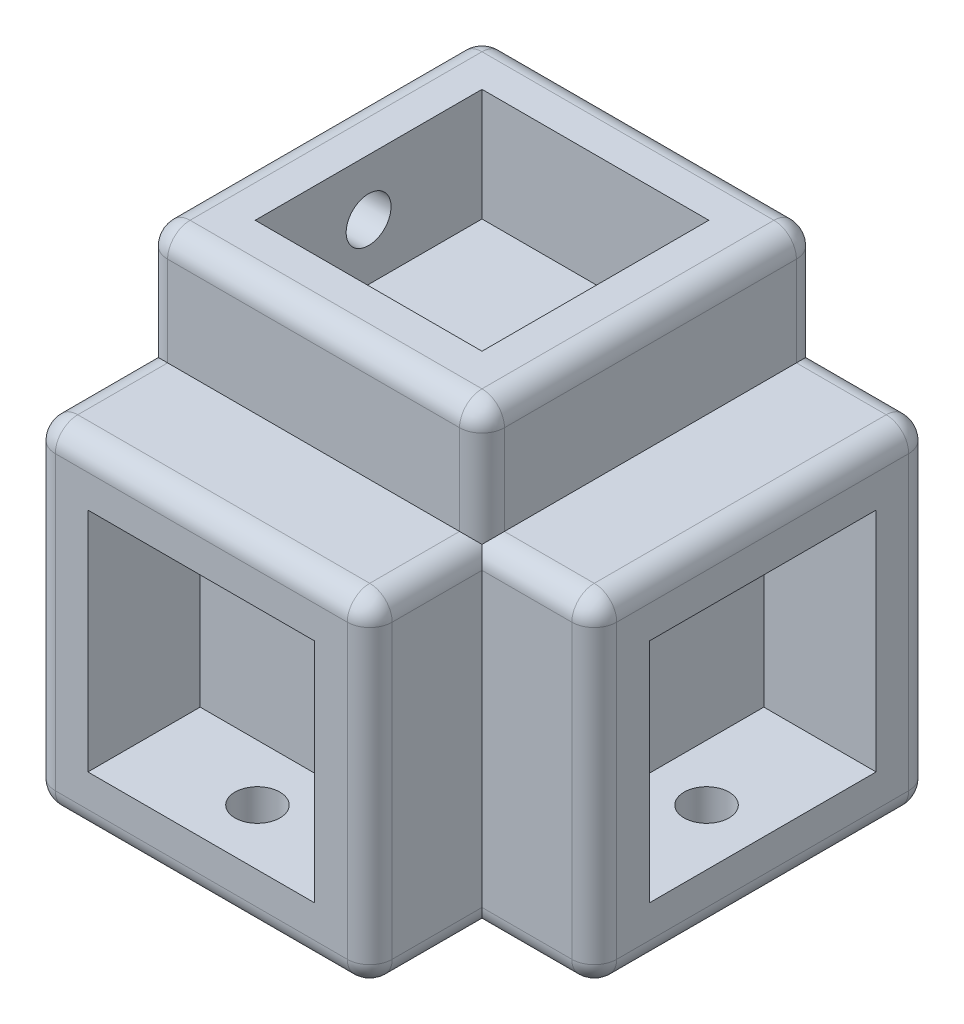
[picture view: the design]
ISO-10303-21;
HEADER;
FILE_DESCRIPTION(('STEP AP214'),'2;1');
FILE_NAME('part.step','',(''),(''),'','','');
FILE_SCHEMA(('AUTOMOTIVE_DESIGN { 1 0 10303 214 1 1 1 1 }'));
ENDSEC;
DATA;
#1=APPLICATION_CONTEXT('core data for automotive mechanical design processes');
#2=APPLICATION_PROTOCOL_DEFINITION('international standard','automotive_design',2000,#1);
#3=PRODUCT_CONTEXT('',#1,'mechanical');
#4=PRODUCT('Part','Part','',(#3));
#5=PRODUCT_RELATED_PRODUCT_CATEGORY('part','',(#4));
#6=PRODUCT_DEFINITION_FORMATION('','',#4);
#7=PRODUCT_DEFINITION_CONTEXT('part definition',#1,'design');
#8=PRODUCT_DEFINITION('design','',#6,#7);
#9=PRODUCT_DEFINITION_SHAPE('','',#8);
#10=(LENGTH_UNIT() NAMED_UNIT(*) SI_UNIT(.MILLI.,.METRE.));
#11=(NAMED_UNIT(*) PLANE_ANGLE_UNIT() SI_UNIT($,.RADIAN.));
#12=(NAMED_UNIT(*) SI_UNIT($,.STERADIAN.) SOLID_ANGLE_UNIT());
#13=UNCERTAINTY_MEASURE_WITH_UNIT(LENGTH_MEASURE(1.E-05),#10,'distance_accuracy_value','');
#14=(GEOMETRIC_REPRESENTATION_CONTEXT(3) GLOBAL_UNCERTAINTY_ASSIGNED_CONTEXT((#13)) GLOBAL_UNIT_ASSIGNED_CONTEXT((#10,
#11,#12)) REPRESENTATION_CONTEXT('',''));
#15=CARTESIAN_POINT('',(0.,0.,0.));
#16=DIRECTION('',(0.,0.,1.));
#17=DIRECTION('',(1.,0.,0.));
#18=AXIS2_PLACEMENT_3D('',#15,#16,#17);
#19=CARTESIAN_POINT('',(0.,0.,30.));
#20=DIRECTION('',(0.,0.,1.));
#21=DIRECTION('',(1.,0.,0.));
#22=AXIS2_PLACEMENT_3D('',#19,#20,#21);
#23=PLANE('',#22);
#24=DIRECTION('',(-1.,0.,0.));
#25=VECTOR('',#24,1.);
#26=CARTESIAN_POINT('',(0.,2.,30.));
#27=LINE('',#26,#25);
#28=CARTESIAN_POINT('',(30.,2.00000000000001,30.));
#29=VERTEX_POINT('',#28);
#30=CARTESIAN_POINT('',(38.,2.,30.));
#31=VERTEX_POINT('',#30);
#32=EDGE_CURVE('E499',#29,#31,#27,.F.);
#33=ORIENTED_EDGE('',*,*,#32,.T.);
#34=DIRECTION('',(0.,1.,0.));
#35=VECTOR('',#34,1.);
#36=CARTESIAN_POINT('',(38.,28.,30.));
#37=LINE('',#36,#35);
#38=CARTESIAN_POINT('',(38.,28.,30.));
#39=VERTEX_POINT('',#38);
#40=EDGE_CURVE('E721',#31,#39,#37,.T.);
#41=ORIENTED_EDGE('',*,*,#40,.T.);
#42=DIRECTION('',(-1.,0.,0.));
#43=VECTOR('',#42,1.);
#44=CARTESIAN_POINT('',(30.,28.,30.));
#45=LINE('',#44,#43);
#46=CARTESIAN_POINT('',(30.,28.,30.));
#47=VERTEX_POINT('',#46);
#48=EDGE_CURVE('E451',#39,#47,#45,.T.);
#49=ORIENTED_EDGE('',*,*,#48,.T.);
#50=DIRECTION('',(0.,1.,0.));
#51=VECTOR('',#50,1.);
#52=CARTESIAN_POINT('',(30.,30.,30.));
#53=LINE('',#52,#51);
#54=EDGE_CURVE('E423',#29,#47,#53,.T.);
#55=ORIENTED_EDGE('',*,*,#54,.F.);
#56=EDGE_LOOP('',(#33,#41,#49,#55));
#57=FACE_BOUND('',#56,.T.);
#58=ADVANCED_FACE('F47',(#57),#23,.T.);
#59=CARTESIAN_POINT('',(40.,0.,30.));
#60=DIRECTION('',(0.,-1.,0.));
#61=DIRECTION('',(0.,0.,-1.));
#62=AXIS2_PLACEMENT_3D('',#59,#60,#61);
#63=PLANE('',#62);
#64=CARTESIAN_POINT('',(15.,0.,35.));
#65=DIRECTION('',(0.,-1.,0.));
#66=DIRECTION('',(0.,0.,-1.));
#67=AXIS2_PLACEMENT_3D('',#64,#65,#66);
#68=CIRCLE('',#67,2.00000000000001);
#69=CARTESIAN_POINT('',(15.,0.,33.));
#70=VERTEX_POINT('',#69);
#71=EDGE_CURVE('E1531',#70,#70,#68,.T.);
#72=ORIENTED_EDGE('',*,*,#71,.F.);
#73=EDGE_LOOP('',(#72));
#74=FACE_BOUND('',#73,.T.);
#75=CARTESIAN_POINT('',(35.,0.,15.));
#76=DIRECTION('',(0.,-1.,0.));
#77=DIRECTION('',(0.,0.,-1.));
#78=AXIS2_PLACEMENT_3D('',#75,#76,#77);
#79=CIRCLE('',#78,2.);
#80=CARTESIAN_POINT('',(35.,0.,13.));
#81=VERTEX_POINT('',#80);
#82=EDGE_CURVE('E1519',#81,#81,#79,.T.);
#83=ORIENTED_EDGE('',*,*,#82,.F.);
#84=EDGE_LOOP('',(#83));
#85=FACE_BOUND('',#84,.T.);
#86=DIRECTION('',(-1.,0.,0.));
#87=VECTOR('',#86,1.);
#88=CARTESIAN_POINT('',(40.,0.,2.));
#89=LINE('',#88,#87);
#90=CARTESIAN_POINT('',(2.,0.,2.));
#91=VERTEX_POINT('',#90);
#92=CARTESIAN_POINT('',(38.,0.,2.));
#93=VERTEX_POINT('',#92);
#94=EDGE_CURVE('E602',#91,#93,#89,.F.);
#95=ORIENTED_EDGE('',*,*,#94,.T.);
#96=DIRECTION('',(0.,0.,-1.));
#97=VECTOR('',#96,1.);
#98=CARTESIAN_POINT('',(38.,0.,28.));
#99=LINE('',#98,#97);
#100=CARTESIAN_POINT('',(38.,0.,28.));
#101=VERTEX_POINT('',#100);
#102=EDGE_CURVE('E715',#93,#101,#99,.F.);
#103=ORIENTED_EDGE('',*,*,#102,.T.);
#104=DIRECTION('',(-1.,0.,0.));
#105=VECTOR('',#104,1.);
#106=CARTESIAN_POINT('',(40.,0.,28.));
#107=LINE('',#106,#105);
#108=CARTESIAN_POINT('',(28.,0.,28.));
#109=VERTEX_POINT('',#108);
#110=EDGE_CURVE('E496',#101,#109,#107,.T.);
#111=ORIENTED_EDGE('',*,*,#110,.T.);
#112=DIRECTION('',(0.,0.,-1.));
#113=VECTOR('',#112,1.);
#114=CARTESIAN_POINT('',(28.,0.,40.));
#115=LINE('',#114,#113);
#116=CARTESIAN_POINT('',(28.,0.,38.));
#117=VERTEX_POINT('',#116);
#118=EDGE_CURVE('E488',#109,#117,#115,.F.);
#119=ORIENTED_EDGE('',*,*,#118,.T.);
#120=DIRECTION('',(1.,0.,0.));
#121=VECTOR('',#120,1.);
#122=CARTESIAN_POINT('',(0.,0.,38.));
#123=LINE('',#122,#121);
#124=CARTESIAN_POINT('',(2.,0.,38.));
#125=VERTEX_POINT('',#124);
#126=EDGE_CURVE('E520',#117,#125,#123,.F.);
#127=ORIENTED_EDGE('',*,*,#126,.T.);
#128=DIRECTION('',(0.,0.,-1.));
#129=VECTOR('',#128,1.);
#130=CARTESIAN_POINT('',(2.,0.,0.));
#131=LINE('',#130,#129);
#132=EDGE_CURVE('E567',#125,#91,#131,.T.);
#133=ORIENTED_EDGE('',*,*,#132,.T.);
#134=EDGE_LOOP('',(#95,#103,#111,#119,#127,#133));
#135=FACE_BOUND('',#134,.T.);
#136=ADVANCED_FACE('F815',(#74,#85,#135),#63,.T.);
#137=CARTESIAN_POINT('',(40.,0.,30.));
#138=DIRECTION('',(-1.,0.,0.));
#139=DIRECTION('',(0.,-1.,0.));
#140=AXIS2_PLACEMENT_3D('',#137,#138,#139);
#141=PLANE('',#140);
#142=DIRECTION('',(0.,1.,0.));
#143=VECTOR('',#142,1.);
#144=CARTESIAN_POINT('',(40.,2.,28.));
#145=LINE('',#144,#143);
#146=CARTESIAN_POINT('',(40.,28.,28.));
#147=VERTEX_POINT('',#146);
#148=CARTESIAN_POINT('',(40.,2.,28.));
#149=VERTEX_POINT('',#148);
#150=EDGE_CURVE('E708',#147,#149,#145,.F.);
#151=ORIENTED_EDGE('',*,*,#150,.T.);
#152=DIRECTION('',(0.,0.,-1.));
#153=VECTOR('',#152,1.);
#154=CARTESIAN_POINT('',(40.,2.,2.));
#155=LINE('',#154,#153);
#156=CARTESIAN_POINT('',(40.,2.,2.));
#157=VERTEX_POINT('',#156);
#158=EDGE_CURVE('E711',#149,#157,#155,.T.);
#159=ORIENTED_EDGE('',*,*,#158,.T.);
#160=DIRECTION('',(0.,1.,0.));
#161=VECTOR('',#160,1.);
#162=CARTESIAN_POINT('',(40.,0.,2.));
#163=LINE('',#162,#161);
#164=CARTESIAN_POINT('',(40.,28.,2.));
#165=VERTEX_POINT('',#164);
#166=EDGE_CURVE('E702',#157,#165,#163,.T.);
#167=ORIENTED_EDGE('',*,*,#166,.T.);
#168=DIRECTION('',(0.,0.,-1.));
#169=VECTOR('',#168,1.);
#170=CARTESIAN_POINT('',(40.,28.,30.));
#171=LINE('',#170,#169);
#172=EDGE_CURVE('E705',#165,#147,#171,.F.);
#173=ORIENTED_EDGE('',*,*,#172,.T.);
#174=EDGE_LOOP('',(#151,#159,#167,#173));
#175=FACE_BOUND('',#174,.T.);
#176=DIRECTION('',(0.,0.,1.));
#177=VECTOR('',#176,1.);
#178=CARTESIAN_POINT('',(40.,25.1,25.1));
#179=LINE('',#178,#177);
#180=CARTESIAN_POINT('',(40.,25.1,4.9));
#181=VERTEX_POINT('',#180);
#182=CARTESIAN_POINT('',(40.,25.1,25.1));
#183=VERTEX_POINT('',#182);
#184=EDGE_CURVE('E365',#181,#183,#179,.T.);
#185=ORIENTED_EDGE('',*,*,#184,.F.);
#186=DIRECTION('',(0.,1.,0.));
#187=VECTOR('',#186,1.);
#188=CARTESIAN_POINT('',(40.,25.1,4.89999999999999));
#189=LINE('',#188,#187);
#190=CARTESIAN_POINT('',(40.,4.9,4.89999999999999));
#191=VERTEX_POINT('',#190);
#192=EDGE_CURVE('E339',#191,#181,#189,.T.);
#193=ORIENTED_EDGE('',*,*,#192,.F.);
#194=DIRECTION('',(0.,0.,-1.));
#195=VECTOR('',#194,1.);
#196=CARTESIAN_POINT('',(40.,4.9,25.1));
#197=LINE('',#196,#195);
#198=CARTESIAN_POINT('',(40.,4.9,25.1));
#199=VERTEX_POINT('',#198);
#200=EDGE_CURVE('E350',#199,#191,#197,.T.);
#201=ORIENTED_EDGE('',*,*,#200,.F.);
#202=DIRECTION('',(0.,-1.,0.));
#203=VECTOR('',#202,1.);
#204=CARTESIAN_POINT('',(40.,25.1,25.1));
#205=LINE('',#204,#203);
#206=EDGE_CURVE('E369',#183,#199,#205,.T.);
#207=ORIENTED_EDGE('',*,*,#206,.F.);
#208=EDGE_LOOP('',(#185,#193,#201,#207));
#209=FACE_BOUND('',#208,.T.);
#210=ADVANCED_FACE('F945',(#175,#209),#141,.F.);
#211=CARTESIAN_POINT('',(40.,30.,30.));
#212=DIRECTION('',(0.,-1.,0.));
#213=DIRECTION('',(1.,0.,0.));
#214=AXIS2_PLACEMENT_3D('',#211,#212,#213);
#215=PLANE('',#214);
#216=DIRECTION('',(-1.,0.,0.));
#217=VECTOR('',#216,1.);
#218=CARTESIAN_POINT('',(40.,30.,28.));
#219=LINE('',#218,#217);
#220=CARTESIAN_POINT('',(30.,30.,28.));
#221=VERTEX_POINT('',#220);
#222=CARTESIAN_POINT('',(38.,30.,28.));
#223=VERTEX_POINT('',#222);
#224=EDGE_CURVE('E454',#221,#223,#219,.F.);
#225=ORIENTED_EDGE('',*,*,#224,.T.);
#226=DIRECTION('',(0.,0.,-1.));
#227=VECTOR('',#226,1.);
#228=CARTESIAN_POINT('',(38.,30.,30.));
#229=LINE('',#228,#227);
#230=CARTESIAN_POINT('',(38.,30.,2.));
#231=VERTEX_POINT('',#230);
#232=EDGE_CURVE('E72',#223,#231,#229,.T.);
#233=ORIENTED_EDGE('',*,*,#232,.T.);
#234=DIRECTION('',(-1.,0.,0.));
#235=VECTOR('',#234,1.);
#236=CARTESIAN_POINT('',(40.,30.,2.));
#237=LINE('',#236,#235);
#238=CARTESIAN_POINT('',(30.,30.,2.));
#239=VERTEX_POINT('',#238);
#240=EDGE_CURVE('E475',#231,#239,#237,.T.);
#241=ORIENTED_EDGE('',*,*,#240,.T.);
#242=DIRECTION('',(0.,0.,-1.));
#243=VECTOR('',#242,1.);
#244=CARTESIAN_POINT('',(30.,30.,30.));
#245=LINE('',#244,#243);
#246=EDGE_CURVE('E440',#221,#239,#245,.T.);
#247=ORIENTED_EDGE('',*,*,#246,.F.);
#248=EDGE_LOOP('',(#225,#233,#241,#247));
#249=FACE_BOUND('',#248,.T.);
#250=ADVANCED_FACE('F774',(#249),#215,.F.);
#251=CARTESIAN_POINT('',(30.,40.,30.));
#252=DIRECTION('',(1.,0.,0.));
#253=DIRECTION('',(0.,0.,-1.));
#254=AXIS2_PLACEMENT_3D('',#251,#252,#253);
#255=PLANE('',#254);
#256=DIRECTION('',(0.,-1.,0.));
#257=VECTOR('',#256,1.);
#258=CARTESIAN_POINT('',(30.,40.,2.));
#259=LINE('',#258,#257);
#260=CARTESIAN_POINT('',(30.,38.,2.));
#261=VERTEX_POINT('',#260);
#262=EDGE_CURVE('E484',#239,#261,#259,.F.);
#263=ORIENTED_EDGE('',*,*,#262,.T.);
#264=DIRECTION('',(0.,0.,-1.));
#265=VECTOR('',#264,1.);
#266=CARTESIAN_POINT('',(30.,38.,30.));
#267=LINE('',#266,#265);
#268=CARTESIAN_POINT('',(30.,38.,28.));
#269=VERTEX_POINT('',#268);
#270=EDGE_CURVE('E643',#261,#269,#267,.F.);
#271=ORIENTED_EDGE('',*,*,#270,.T.);
#272=DIRECTION('',(0.,-1.,0.));
#273=VECTOR('',#272,1.);
#274=CARTESIAN_POINT('',(30.,40.,28.));
#275=LINE('',#274,#273);
#276=EDGE_CURVE('E457',#269,#221,#275,.T.);
#277=ORIENTED_EDGE('',*,*,#276,.T.);
#278=ORIENTED_EDGE('',*,*,#246,.T.);
#279=EDGE_LOOP('',(#263,#271,#277,#278));
#280=FACE_BOUND('',#279,.T.);
#281=ADVANCED_FACE('F776',(#280),#255,.T.);
#282=CARTESIAN_POINT('',(0.,40.,30.));
#283=DIRECTION('',(0.,1.,0.));
#284=DIRECTION('',(0.,0.,1.));
#285=AXIS2_PLACEMENT_3D('',#282,#283,#284);
#286=PLANE('',#285);
#287=DIRECTION('',(1.,0.,0.));
#288=VECTOR('',#287,1.);
#289=CARTESIAN_POINT('',(0.,40.,2.));
#290=LINE('',#289,#288);
#291=CARTESIAN_POINT('',(28.,40.,2.));
#292=VERTEX_POINT('',#291);
#293=CARTESIAN_POINT('',(2.,40.,2.));
#294=VERTEX_POINT('',#293);
#295=EDGE_CURVE('E612',#292,#294,#290,.F.);
#296=ORIENTED_EDGE('',*,*,#295,.T.);
#297=DIRECTION('',(0.,0.,-1.));
#298=VECTOR('',#297,1.);
#299=CARTESIAN_POINT('',(2.,40.,30.));
#300=LINE('',#299,#298);
#301=CARTESIAN_POINT('',(2.,40.,28.));
#302=VERTEX_POINT('',#301);
#303=EDGE_CURVE('E619',#294,#302,#300,.F.);
#304=ORIENTED_EDGE('',*,*,#303,.T.);
#305=DIRECTION('',(1.,0.,0.));
#306=VECTOR('',#305,1.);
#307=CARTESIAN_POINT('',(0.,40.,28.));
#308=LINE('',#307,#306);
#309=CARTESIAN_POINT('',(28.,40.,28.));
#310=VERTEX_POINT('',#309);
#311=EDGE_CURVE('E615',#302,#310,#308,.T.);
#312=ORIENTED_EDGE('',*,*,#311,.T.);
#313=DIRECTION('',(0.,0.,-1.));
#314=VECTOR('',#313,1.);
#315=CARTESIAN_POINT('',(28.,40.,30.));
#316=LINE('',#315,#314);
#317=EDGE_CURVE('E609',#310,#292,#316,.T.);
#318=ORIENTED_EDGE('',*,*,#317,.T.);
#319=EDGE_LOOP('',(#296,#304,#312,#318));
#320=FACE_BOUND('',#319,.T.);
#321=DIRECTION('',(0.,0.,-1.));
#322=VECTOR('',#321,1.);
#323=CARTESIAN_POINT('',(25.1,40.,4.9));
#324=LINE('',#323,#322);
#325=CARTESIAN_POINT('',(25.1,40.,25.1));
#326=VERTEX_POINT('',#325);
#327=CARTESIAN_POINT('',(25.1,40.,4.9));
#328=VERTEX_POINT('',#327);
#329=EDGE_CURVE('E293',#326,#328,#324,.T.);
#330=ORIENTED_EDGE('',*,*,#329,.F.);
#331=DIRECTION('',(1.,0.,0.));
#332=VECTOR('',#331,1.);
#333=CARTESIAN_POINT('',(4.9,40.,25.1));
#334=LINE('',#333,#332);
#335=CARTESIAN_POINT('',(4.9,40.,25.1));
#336=VERTEX_POINT('',#335);
#337=EDGE_CURVE('E313',#336,#326,#334,.T.);
#338=ORIENTED_EDGE('',*,*,#337,.F.);
#339=DIRECTION('',(0.,0.,1.));
#340=VECTOR('',#339,1.);
#341=CARTESIAN_POINT('',(4.9,40.,4.9));
#342=LINE('',#341,#340);
#343=CARTESIAN_POINT('',(4.9,40.,4.9));
#344=VERTEX_POINT('',#343);
#345=EDGE_CURVE('E317',#344,#336,#342,.T.);
#346=ORIENTED_EDGE('',*,*,#345,.F.);
#347=DIRECTION('',(-1.,0.,0.));
#348=VECTOR('',#347,1.);
#349=CARTESIAN_POINT('',(4.9,40.,4.9));
#350=LINE('',#349,#348);
#351=EDGE_CURVE('E329',#328,#344,#350,.T.);
#352=ORIENTED_EDGE('',*,*,#351,.F.);
#353=EDGE_LOOP('',(#330,#338,#346,#352));
#354=FACE_BOUND('',#353,.T.);
#355=ADVANCED_FACE('F872',(#320,#354),#286,.T.);
#356=CARTESIAN_POINT('',(0.,40.,30.));
#357=DIRECTION('',(1.,0.,0.));
#358=DIRECTION('',(0.,1.,0.));
#359=AXIS2_PLACEMENT_3D('',#356,#357,#358);
#360=PLANE('',#359);
#361=CARTESIAN_POINT('',(0.,35.,15.));
#362=DIRECTION('',(-1.,0.,0.));
#363=DIRECTION('',(0.,-1.,0.));
#364=AXIS2_PLACEMENT_3D('',#361,#362,#363);
#365=CIRCLE('',#364,2.);
#366=CARTESIAN_POINT('',(0.,33.,15.));
#367=VERTEX_POINT('',#366);
#368=EDGE_CURVE('E1515',#367,#367,#365,.T.);
#369=ORIENTED_EDGE('',*,*,#368,.F.);
#370=EDGE_LOOP('',(#369));
#371=FACE_BOUND('',#370,.T.);
#372=DIRECTION('',(0.,0.,-1.));
#373=VECTOR('',#372,1.);
#374=CARTESIAN_POINT('',(0.,38.,0.));
#375=LINE('',#374,#373);
#376=CARTESIAN_POINT('',(0.,38.,28.));
#377=VERTEX_POINT('',#376);
#378=CARTESIAN_POINT('',(0.,38.,2.));
#379=VERTEX_POINT('',#378);
#380=EDGE_CURVE('E637',#377,#379,#375,.T.);
#381=ORIENTED_EDGE('',*,*,#380,.T.);
#382=DIRECTION('',(0.,-1.,0.));
#383=VECTOR('',#382,1.);
#384=CARTESIAN_POINT('',(0.,40.,2.));
#385=LINE('',#384,#383);
#386=CARTESIAN_POINT('',(0.,2.,2.));
#387=VERTEX_POINT('',#386);
#388=EDGE_CURVE('E640',#379,#387,#385,.T.);
#389=ORIENTED_EDGE('',*,*,#388,.T.);
#390=DIRECTION('',(0.,0.,-1.));
#391=VECTOR('',#390,1.);
#392=CARTESIAN_POINT('',(0.,2.,38.));
#393=LINE('',#392,#391);
#394=CARTESIAN_POINT('',(0.,2.,38.));
#395=VERTEX_POINT('',#394);
#396=EDGE_CURVE('E555',#387,#395,#393,.F.);
#397=ORIENTED_EDGE('',*,*,#396,.T.);
#398=DIRECTION('',(0.,-1.,0.));
#399=VECTOR('',#398,1.);
#400=CARTESIAN_POINT('',(0.,40.,38.));
#401=LINE('',#400,#399);
#402=CARTESIAN_POINT('',(0.,28.,38.));
#403=VERTEX_POINT('',#402);
#404=EDGE_CURVE('E536',#395,#403,#401,.F.);
#405=ORIENTED_EDGE('',*,*,#404,.T.);
#406=DIRECTION('',(0.,0.,-1.));
#407=VECTOR('',#406,1.);
#408=CARTESIAN_POINT('',(0.,28.,30.));
#409=LINE('',#408,#407);
#410=CARTESIAN_POINT('',(0.,28.,28.));
#411=VERTEX_POINT('',#410);
#412=EDGE_CURVE('E558',#403,#411,#409,.T.);
#413=ORIENTED_EDGE('',*,*,#412,.T.);
#414=DIRECTION('',(0.,-1.,0.));
#415=VECTOR('',#414,1.);
#416=CARTESIAN_POINT('',(0.,40.,28.));
#417=LINE('',#416,#415);
#418=EDGE_CURVE('E634',#411,#377,#417,.F.);
#419=ORIENTED_EDGE('',*,*,#418,.T.);
#420=EDGE_LOOP('',(#381,#389,#397,#405,#413,#419));
#421=FACE_BOUND('',#420,.T.);
#422=ADVANCED_FACE('F833',(#371,#421),#360,.F.);
#423=DIRECTION('',(0.,-1.,0.));
#424=VECTOR('',#423,1.);
#425=CARTESIAN_POINT('',(28.,0.,30.));
#426=LINE('',#425,#424);
#427=CARTESIAN_POINT('',(28.,30.,30.));
#428=VERTEX_POINT('',#427);
#429=CARTESIAN_POINT('',(28.,38.,30.));
#430=VERTEX_POINT('',#429);
#431=EDGE_CURVE('E460',#428,#430,#426,.F.);
#432=ORIENTED_EDGE('',*,*,#431,.T.);
#433=DIRECTION('',(1.,0.,0.));
#434=VECTOR('',#433,1.);
#435=CARTESIAN_POINT('',(0.,38.,30.));
#436=LINE('',#435,#434);
#437=CARTESIAN_POINT('',(2.,38.,30.));
#438=VERTEX_POINT('',#437);
#439=EDGE_CURVE('E625',#430,#438,#436,.F.);
#440=ORIENTED_EDGE('',*,*,#439,.T.);
#441=DIRECTION('',(0.,-1.,0.));
#442=VECTOR('',#441,1.);
#443=CARTESIAN_POINT('',(2.,28.,30.));
#444=LINE('',#443,#442);
#445=CARTESIAN_POINT('',(2.,30.,30.));
#446=VERTEX_POINT('',#445);
#447=EDGE_CURVE('E622',#438,#446,#444,.T.);
#448=ORIENTED_EDGE('',*,*,#447,.T.);
#449=DIRECTION('',(-1.,0.,0.));
#450=VECTOR('',#449,1.);
#451=CARTESIAN_POINT('',(30.,30.,30.));
#452=LINE('',#451,#450);
#453=EDGE_CURVE('E436',#428,#446,#452,.T.);
#454=ORIENTED_EDGE('',*,*,#453,.F.);
#455=EDGE_LOOP('',(#432,#440,#448,#454));
#456=FACE_BOUND('',#455,.T.);
#457=ADVANCED_FACE('F888',(#456),#23,.T.);
#458=CARTESIAN_POINT('',(0.,0.,0.));
#459=DIRECTION('',(0.,0.,1.));
#460=DIRECTION('',(1.,0.,0.));
#461=AXIS2_PLACEMENT_3D('',#458,#459,#460);
#462=PLANE('',#461);
#463=CARTESIAN_POINT('',(15.13,23.,0.));
#464=DIRECTION('',(0.,0.,-1.));
#465=DIRECTION('',(-1.,0.,0.));
#466=AXIS2_PLACEMENT_3D('',#463,#464,#465);
#467=CIRCLE('',#466,2.5);
#468=CARTESIAN_POINT('',(12.63,23.,0.));
#469=VERTEX_POINT('',#468);
#470=EDGE_CURVE('E1537',#469,#469,#467,.T.);
#471=ORIENTED_EDGE('',*,*,#470,.F.);
#472=EDGE_LOOP('',(#471));
#473=FACE_BOUND('',#472,.T.);
#474=CARTESIAN_POINT('',(15.13,8.,0.));
#475=DIRECTION('',(0.,0.,-1.));
#476=DIRECTION('',(-1.,0.,0.));
#477=AXIS2_PLACEMENT_3D('',#474,#475,#476);
#478=CIRCLE('',#477,2.5);
#479=CARTESIAN_POINT('',(12.63,8.,0.));
#480=VERTEX_POINT('',#479);
#481=EDGE_CURVE('E1540',#480,#480,#478,.T.);
#482=ORIENTED_EDGE('',*,*,#481,.F.);
#483=EDGE_LOOP('',(#482));
#484=FACE_BOUND('',#483,.T.);
#485=DIRECTION('',(-1.,0.,0.));
#486=VECTOR('',#485,1.);
#487=CARTESIAN_POINT('',(0.,28.,0.));
#488=LINE('',#487,#486);
#489=CARTESIAN_POINT('',(28.,28.,0.));
#490=VERTEX_POINT('',#489);
#491=CARTESIAN_POINT('',(38.,28.,0.));
#492=VERTEX_POINT('',#491);
#493=EDGE_CURVE('E481',#490,#492,#488,.F.);
#494=ORIENTED_EDGE('',*,*,#493,.T.);
#495=DIRECTION('',(0.,1.,0.));
#496=VECTOR('',#495,1.);
#497=CARTESIAN_POINT('',(38.,0.,0.));
#498=LINE('',#497,#496);
#499=CARTESIAN_POINT('',(38.,2.,0.));
#500=VERTEX_POINT('',#499);
#501=EDGE_CURVE('E11',#492,#500,#498,.F.);
#502=ORIENTED_EDGE('',*,*,#501,.T.);
#503=DIRECTION('',(-1.,0.,0.));
#504=VECTOR('',#503,1.);
#505=CARTESIAN_POINT('',(2.,2.,0.));
#506=LINE('',#505,#504);
#507=CARTESIAN_POINT('',(2.,2.,0.));
#508=VERTEX_POINT('',#507);
#509=EDGE_CURVE('E599',#500,#508,#506,.T.);
#510=ORIENTED_EDGE('',*,*,#509,.T.);
#511=DIRECTION('',(0.,-1.,0.));
#512=VECTOR('',#511,1.);
#513=CARTESIAN_POINT('',(2.,0.,0.));
#514=LINE('',#513,#512);
#515=CARTESIAN_POINT('',(2.,38.,0.));
#516=VERTEX_POINT('',#515);
#517=EDGE_CURVE('E577',#508,#516,#514,.F.);
#518=ORIENTED_EDGE('',*,*,#517,.T.);
#519=DIRECTION('',(1.,0.,0.));
#520=VECTOR('',#519,1.);
#521=CARTESIAN_POINT('',(28.,38.,0.));
#522=LINE('',#521,#520);
#523=CARTESIAN_POINT('',(28.,38.,0.));
#524=VERTEX_POINT('',#523);
#525=EDGE_CURVE('E596',#516,#524,#522,.T.);
#526=ORIENTED_EDGE('',*,*,#525,.T.);
#527=DIRECTION('',(0.,-1.,0.));
#528=VECTOR('',#527,1.);
#529=CARTESIAN_POINT('',(28.,30.,0.));
#530=LINE('',#529,#528);
#531=EDGE_CURVE('E478',#524,#490,#530,.T.);
#532=ORIENTED_EDGE('',*,*,#531,.T.);
#533=EDGE_LOOP('',(#494,#502,#510,#518,#526,#532));
#534=FACE_BOUND('',#533,.T.);
#535=ADVANCED_FACE('F855',(#473,#484,#534),#462,.F.);
#536=CARTESIAN_POINT('',(30.,30.,40.));
#537=DIRECTION('',(-1.,0.,0.));
#538=DIRECTION('',(0.,-1.,0.));
#539=AXIS2_PLACEMENT_3D('',#536,#537,#538);
#540=PLANE('',#539);
#541=DIRECTION('',(0.,0.,-1.));
#542=VECTOR('',#541,1.);
#543=CARTESIAN_POINT('',(30.,28.,40.));
#544=LINE('',#543,#542);
#545=CARTESIAN_POINT('',(30.,28.,38.));
#546=VERTEX_POINT('',#545);
#547=EDGE_CURVE('E447',#47,#546,#544,.F.);
#548=ORIENTED_EDGE('',*,*,#547,.T.);
#549=DIRECTION('',(0.,1.,0.));
#550=VECTOR('',#549,1.);
#551=CARTESIAN_POINT('',(30.,30.,38.));
#552=LINE('',#551,#550);
#553=CARTESIAN_POINT('',(30.,2.,38.));
#554=VERTEX_POINT('',#553);
#555=EDGE_CURVE('E533',#546,#554,#552,.F.);
#556=ORIENTED_EDGE('',*,*,#555,.T.);
#557=DIRECTION('',(0.,0.,-1.));
#558=VECTOR('',#557,1.);
#559=CARTESIAN_POINT('',(30.,2.,30.));
#560=LINE('',#559,#558);
#561=EDGE_CURVE('E503',#554,#29,#560,.T.);
#562=ORIENTED_EDGE('',*,*,#561,.T.);
#563=ORIENTED_EDGE('',*,*,#54,.T.);
#564=EDGE_LOOP('',(#548,#556,#562,#563));
#565=FACE_BOUND('',#564,.T.);
#566=ADVANCED_FACE('F794',(#565),#540,.F.);
#567=CARTESIAN_POINT('',(30.,30.,40.));
#568=DIRECTION('',(0.,-1.,0.));
#569=DIRECTION('',(1.,0.,0.));
#570=AXIS2_PLACEMENT_3D('',#567,#568,#569);
#571=PLANE('',#570);
#572=ORIENTED_EDGE('',*,*,#453,.T.);
#573=DIRECTION('',(0.,0.,-1.));
#574=VECTOR('',#573,1.);
#575=CARTESIAN_POINT('',(2.,30.,40.));
#576=LINE('',#575,#574);
#577=CARTESIAN_POINT('',(2.,30.,38.));
#578=VERTEX_POINT('',#577);
#579=EDGE_CURVE('E561',#446,#578,#576,.F.);
#580=ORIENTED_EDGE('',*,*,#579,.T.);
#581=DIRECTION('',(-1.,0.,0.));
#582=VECTOR('',#581,1.);
#583=CARTESIAN_POINT('',(30.,30.,38.));
#584=LINE('',#583,#582);
#585=CARTESIAN_POINT('',(28.,30.,38.));
#586=VERTEX_POINT('',#585);
#587=EDGE_CURVE('E527',#578,#586,#584,.F.);
#588=ORIENTED_EDGE('',*,*,#587,.T.);
#589=DIRECTION('',(0.,0.,-1.));
#590=VECTOR('',#589,1.);
#591=CARTESIAN_POINT('',(28.,30.,40.));
#592=LINE('',#591,#590);
#593=EDGE_CURVE('E444',#586,#428,#592,.T.);
#594=ORIENTED_EDGE('',*,*,#593,.T.);
#595=EDGE_LOOP('',(#572,#580,#588,#594));
#596=FACE_BOUND('',#595,.T.);
#597=ADVANCED_FACE('F891',(#596),#571,.F.);
#598=CARTESIAN_POINT('',(0.,0.,40.));
#599=DIRECTION('',(0.,0.,-1.));
#600=DIRECTION('',(-1.,0.,0.));
#601=AXIS2_PLACEMENT_3D('',#598,#599,#600);
#602=PLANE('',#601);
#603=DIRECTION('',(-1.,0.,0.));
#604=VECTOR('',#603,1.);
#605=CARTESIAN_POINT('',(0.,28.,40.));
#606=LINE('',#605,#604);
#607=CARTESIAN_POINT('',(28.,28.,40.));
#608=VERTEX_POINT('',#607);
#609=CARTESIAN_POINT('',(2.,28.,40.));
#610=VERTEX_POINT('',#609);
#611=EDGE_CURVE('E513',#608,#610,#606,.T.);
#612=ORIENTED_EDGE('',*,*,#611,.T.);
#613=DIRECTION('',(0.,-1.,0.));
#614=VECTOR('',#613,1.);
#615=CARTESIAN_POINT('',(2.,0.,40.));
#616=LINE('',#615,#614);
#617=CARTESIAN_POINT('',(2.,2.,40.));
#618=VERTEX_POINT('',#617);
#619=EDGE_CURVE('E574',#610,#618,#616,.T.);
#620=ORIENTED_EDGE('',*,*,#619,.T.);
#621=DIRECTION('',(1.,0.,0.));
#622=VECTOR('',#621,1.);
#623=CARTESIAN_POINT('',(28.,2.,40.));
#624=LINE('',#623,#622);
#625=CARTESIAN_POINT('',(28.,2.,40.));
#626=VERTEX_POINT('',#625);
#627=EDGE_CURVE('E517',#618,#626,#624,.T.);
#628=ORIENTED_EDGE('',*,*,#627,.T.);
#629=DIRECTION('',(0.,1.,0.));
#630=VECTOR('',#629,1.);
#631=CARTESIAN_POINT('',(28.,0.,40.));
#632=LINE('',#631,#630);
#633=EDGE_CURVE('E506',#626,#608,#632,.T.);
#634=ORIENTED_EDGE('',*,*,#633,.T.);
#635=EDGE_LOOP('',(#612,#620,#628,#634));
#636=FACE_BOUND('',#635,.T.);
#637=DIRECTION('',(-1.,0.,0.));
#638=VECTOR('',#637,1.);
#639=CARTESIAN_POINT('',(4.9,25.1,40.));
#640=LINE('',#639,#638);
#641=CARTESIAN_POINT('',(25.1,25.1,40.));
#642=VERTEX_POINT('',#641);
#643=CARTESIAN_POINT('',(4.9,25.1,40.));
#644=VERTEX_POINT('',#643);
#645=EDGE_CURVE('E409',#642,#644,#640,.T.);
#646=ORIENTED_EDGE('',*,*,#645,.F.);
#647=DIRECTION('',(0.,1.,0.));
#648=VECTOR('',#647,1.);
#649=CARTESIAN_POINT('',(25.1,25.1,40.));
#650=LINE('',#649,#648);
#651=CARTESIAN_POINT('',(25.1,4.9,40.));
#652=VERTEX_POINT('',#651);
#653=EDGE_CURVE('E379',#652,#642,#650,.T.);
#654=ORIENTED_EDGE('',*,*,#653,.F.);
#655=DIRECTION('',(1.,0.,0.));
#656=VECTOR('',#655,1.);
#657=CARTESIAN_POINT('',(4.9,4.9,40.));
#658=LINE('',#657,#656);
#659=CARTESIAN_POINT('',(4.9,4.9,40.));
#660=VERTEX_POINT('',#659);
#661=EDGE_CURVE('E394',#660,#652,#658,.T.);
#662=ORIENTED_EDGE('',*,*,#661,.F.);
#663=DIRECTION('',(0.,-1.,0.));
#664=VECTOR('',#663,1.);
#665=CARTESIAN_POINT('',(4.9,25.1,40.));
#666=LINE('',#665,#664);
#667=EDGE_CURVE('E413',#644,#660,#666,.T.);
#668=ORIENTED_EDGE('',*,*,#667,.F.);
#669=EDGE_LOOP('',(#646,#654,#662,#668));
#670=FACE_BOUND('',#669,.T.);
#671=ADVANCED_FACE('F902',(#636,#670),#602,.F.);
#672=CARTESIAN_POINT('',(25.1,25.1,30.));
#673=DIRECTION('',(1.,0.,0.));
#674=DIRECTION('',(0.,0.,-1.));
#675=AXIS2_PLACEMENT_3D('',#672,#673,#674);
#676=PLANE('',#675);
#677=ORIENTED_EDGE('',*,*,#653,.T.);
#678=DIRECTION('',(0.,0.,1.));
#679=VECTOR('',#678,1.);
#680=CARTESIAN_POINT('',(25.1,25.1,30.));
#681=LINE('',#680,#679);
#682=CARTESIAN_POINT('',(25.1,25.1,30.));
#683=VERTEX_POINT('',#682);
#684=EDGE_CURVE('E406',#683,#642,#681,.T.);
#685=ORIENTED_EDGE('',*,*,#684,.F.);
#686=DIRECTION('',(0.,1.,0.));
#687=VECTOR('',#686,1.);
#688=CARTESIAN_POINT('',(25.1,25.1,30.));
#689=LINE('',#688,#687);
#690=CARTESIAN_POINT('',(25.1,4.9,30.));
#691=VERTEX_POINT('',#690);
#692=EDGE_CURVE('E389',#691,#683,#689,.T.);
#693=ORIENTED_EDGE('',*,*,#692,.F.);
#694=DIRECTION('',(0.,0.,1.));
#695=VECTOR('',#694,1.);
#696=CARTESIAN_POINT('',(25.1,4.9,30.));
#697=LINE('',#696,#695);
#698=EDGE_CURVE('E420',#691,#652,#697,.T.);
#699=ORIENTED_EDGE('',*,*,#698,.T.);
#700=EDGE_LOOP('',(#677,#685,#693,#699));
#701=FACE_BOUND('',#700,.T.);
#702=ADVANCED_FACE('F905',(#701),#676,.F.);
#703=CARTESIAN_POINT('',(4.9,4.9,30.));
#704=DIRECTION('',(0.,-1.,0.));
#705=DIRECTION('',(0.,0.,-1.));
#706=AXIS2_PLACEMENT_3D('',#703,#704,#705);
#707=PLANE('',#706);
#708=CARTESIAN_POINT('',(15.,4.9,35.));
#709=DIRECTION('',(0.,-1.,0.));
#710=DIRECTION('',(0.,0.,-1.));
#711=AXIS2_PLACEMENT_3D('',#708,#709,#710);
#712=CIRCLE('',#711,2.00000000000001);
#713=CARTESIAN_POINT('',(15.,4.9,33.));
#714=VERTEX_POINT('',#713);
#715=EDGE_CURVE('E1527',#714,#714,#712,.T.);
#716=ORIENTED_EDGE('',*,*,#715,.T.);
#717=EDGE_LOOP('',(#716));
#718=FACE_BOUND('',#717,.T.);
#719=ORIENTED_EDGE('',*,*,#661,.T.);
#720=ORIENTED_EDGE('',*,*,#698,.F.);
#721=DIRECTION('',(1.,0.,0.));
#722=VECTOR('',#721,1.);
#723=CARTESIAN_POINT('',(4.9,4.9,30.));
#724=LINE('',#723,#722);
#725=CARTESIAN_POINT('',(4.9,4.9,30.));
#726=VERTEX_POINT('',#725);
#727=EDGE_CURVE('E402',#726,#691,#724,.T.);
#728=ORIENTED_EDGE('',*,*,#727,.F.);
#729=DIRECTION('',(0.,0.,1.));
#730=VECTOR('',#729,1.);
#731=CARTESIAN_POINT('',(4.9,4.9,30.));
#732=LINE('',#731,#730);
#733=EDGE_CURVE('E424',#726,#660,#732,.T.);
#734=ORIENTED_EDGE('',*,*,#733,.T.);
#735=EDGE_LOOP('',(#719,#720,#728,#734));
#736=FACE_BOUND('',#735,.T.);
#737=ADVANCED_FACE('F919',(#718,#736),#707,.F.);
#738=CARTESIAN_POINT('',(4.9,25.1,30.));
#739=DIRECTION('',(-1.,0.,0.));
#740=DIRECTION('',(0.,-1.,0.));
#741=AXIS2_PLACEMENT_3D('',#738,#739,#740);
#742=PLANE('',#741);
#743=ORIENTED_EDGE('',*,*,#667,.T.);
#744=ORIENTED_EDGE('',*,*,#733,.F.);
#745=DIRECTION('',(0.,-1.,0.));
#746=VECTOR('',#745,1.);
#747=CARTESIAN_POINT('',(4.9,25.1,30.));
#748=LINE('',#747,#746);
#749=CARTESIAN_POINT('',(4.9,25.1,30.));
#750=VERTEX_POINT('',#749);
#751=EDGE_CURVE('E398',#750,#726,#748,.T.);
#752=ORIENTED_EDGE('',*,*,#751,.F.);
#753=DIRECTION('',(0.,0.,1.));
#754=VECTOR('',#753,1.);
#755=CARTESIAN_POINT('',(4.9,25.1,30.));
#756=LINE('',#755,#754);
#757=EDGE_CURVE('E427',#750,#644,#756,.T.);
#758=ORIENTED_EDGE('',*,*,#757,.T.);
#759=EDGE_LOOP('',(#743,#744,#752,#758));
#760=FACE_BOUND('',#759,.T.);
#761=ADVANCED_FACE('F921',(#760),#742,.F.);
#762=CARTESIAN_POINT('',(4.9,25.1,30.));
#763=DIRECTION('',(0.,1.,0.));
#764=DIRECTION('',(0.,0.,1.));
#765=AXIS2_PLACEMENT_3D('',#762,#763,#764);
#766=PLANE('',#765);
#767=ORIENTED_EDGE('',*,*,#645,.T.);
#768=ORIENTED_EDGE('',*,*,#757,.F.);
#769=DIRECTION('',(-1.,0.,0.));
#770=VECTOR('',#769,1.);
#771=CARTESIAN_POINT('',(4.9,25.1,30.));
#772=LINE('',#771,#770);
#773=EDGE_CURVE('E393',#683,#750,#772,.T.);
#774=ORIENTED_EDGE('',*,*,#773,.F.);
#775=ORIENTED_EDGE('',*,*,#684,.T.);
#776=EDGE_LOOP('',(#767,#768,#774,#775));
#777=FACE_BOUND('',#776,.T.);
#778=ADVANCED_FACE('F912',(#777),#766,.F.);
#779=CARTESIAN_POINT('',(0.,0.,30.));
#780=DIRECTION('',(0.,0.,1.));
#781=DIRECTION('',(1.,0.,0.));
#782=AXIS2_PLACEMENT_3D('',#779,#780,#781);
#783=PLANE('',#782);
#784=ORIENTED_EDGE('',*,*,#692,.T.);
#785=ORIENTED_EDGE('',*,*,#773,.T.);
#786=ORIENTED_EDGE('',*,*,#751,.T.);
#787=ORIENTED_EDGE('',*,*,#727,.T.);
#788=EDGE_LOOP('',(#784,#785,#786,#787));
#789=FACE_BOUND('',#788,.T.);
#790=ADVANCED_FACE('F923',(#789),#783,.T.);
#791=CARTESIAN_POINT('',(30.,25.1,4.89999999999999));
#792=DIRECTION('',(0.,0.,-1.));
#793=DIRECTION('',(0.,1.,0.));
#794=AXIS2_PLACEMENT_3D('',#791,#792,#793);
#795=PLANE('',#794);
#796=ORIENTED_EDGE('',*,*,#192,.T.);
#797=DIRECTION('',(1.,0.,0.));
#798=VECTOR('',#797,1.);
#799=CARTESIAN_POINT('',(30.,25.1,4.89999999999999));
#800=LINE('',#799,#798);
#801=CARTESIAN_POINT('',(30.,25.1,4.89999999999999));
#802=VERTEX_POINT('',#801);
#803=EDGE_CURVE('E362',#802,#181,#800,.T.);
#804=ORIENTED_EDGE('',*,*,#803,.F.);
#805=DIRECTION('',(0.,1.,0.));
#806=VECTOR('',#805,1.);
#807=CARTESIAN_POINT('',(30.,25.1,4.89999999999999));
#808=LINE('',#807,#806);
#809=CARTESIAN_POINT('',(30.,4.9,4.89999999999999));
#810=VERTEX_POINT('',#809);
#811=EDGE_CURVE('E345',#810,#802,#808,.T.);
#812=ORIENTED_EDGE('',*,*,#811,.F.);
#813=DIRECTION('',(1.,0.,0.));
#814=VECTOR('',#813,1.);
#815=CARTESIAN_POINT('',(30.,4.9,4.89999999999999));
#816=LINE('',#815,#814);
#817=EDGE_CURVE('E376',#810,#191,#816,.T.);
#818=ORIENTED_EDGE('',*,*,#817,.T.);
#819=EDGE_LOOP('',(#796,#804,#812,#818));
#820=FACE_BOUND('',#819,.T.);
#821=ADVANCED_FACE('F925',(#820),#795,.F.);
#822=CARTESIAN_POINT('',(30.,4.9,25.1));
#823=DIRECTION('',(0.,-1.,0.));
#824=DIRECTION('',(1.,0.,0.));
#825=AXIS2_PLACEMENT_3D('',#822,#823,#824);
#826=PLANE('',#825);
#827=CARTESIAN_POINT('',(35.,4.9,15.));
#828=DIRECTION('',(0.,-1.,0.));
#829=DIRECTION('',(1.,0.,0.));
#830=AXIS2_PLACEMENT_3D('',#827,#828,#829);
#831=CIRCLE('',#830,2.);
#832=CARTESIAN_POINT('',(37.,4.9,15.));
#833=VERTEX_POINT('',#832);
#834=EDGE_CURVE('E1514',#833,#833,#831,.T.);
#835=ORIENTED_EDGE('',*,*,#834,.T.);
#836=EDGE_LOOP('',(#835));
#837=FACE_BOUND('',#836,.T.);
#838=ORIENTED_EDGE('',*,*,#200,.T.);
#839=ORIENTED_EDGE('',*,*,#817,.F.);
#840=DIRECTION('',(0.,0.,-1.));
#841=VECTOR('',#840,1.);
#842=CARTESIAN_POINT('',(30.,4.9,25.1));
#843=LINE('',#842,#841);
#844=CARTESIAN_POINT('',(30.,4.9,25.1));
#845=VERTEX_POINT('',#844);
#846=EDGE_CURVE('E358',#845,#810,#843,.T.);
#847=ORIENTED_EDGE('',*,*,#846,.F.);
#848=DIRECTION('',(1.,0.,0.));
#849=VECTOR('',#848,1.);
#850=CARTESIAN_POINT('',(30.,4.9,25.1));
#851=LINE('',#850,#849);
#852=EDGE_CURVE('E380',#845,#199,#851,.T.);
#853=ORIENTED_EDGE('',*,*,#852,.T.);
#854=EDGE_LOOP('',(#838,#839,#847,#853));
#855=FACE_BOUND('',#854,.T.);
#856=ADVANCED_FACE('F931',(#837,#855),#826,.F.);
#857=CARTESIAN_POINT('',(30.,25.1,25.1));
#858=DIRECTION('',(0.,0.,1.));
#859=DIRECTION('',(1.,0.,0.));
#860=AXIS2_PLACEMENT_3D('',#857,#858,#859);
#861=PLANE('',#860);
#862=ORIENTED_EDGE('',*,*,#206,.T.);
#863=ORIENTED_EDGE('',*,*,#852,.F.);
#864=DIRECTION('',(0.,-1.,0.));
#865=VECTOR('',#864,1.);
#866=CARTESIAN_POINT('',(30.,25.1,25.1));
#867=LINE('',#866,#865);
#868=CARTESIAN_POINT('',(30.,25.1,25.1));
#869=VERTEX_POINT('',#868);
#870=EDGE_CURVE('E354',#869,#845,#867,.T.);
#871=ORIENTED_EDGE('',*,*,#870,.F.);
#872=DIRECTION('',(1.,0.,0.));
#873=VECTOR('',#872,1.);
#874=CARTESIAN_POINT('',(30.,25.1,25.1));
#875=LINE('',#874,#873);
#876=EDGE_CURVE('E383',#869,#183,#875,.T.);
#877=ORIENTED_EDGE('',*,*,#876,.T.);
#878=EDGE_LOOP('',(#862,#863,#871,#877));
#879=FACE_BOUND('',#878,.T.);
#880=ADVANCED_FACE('F1173',(#879),#861,.F.);
#881=CARTESIAN_POINT('',(30.,25.1,25.1));
#882=DIRECTION('',(0.,1.,0.));
#883=DIRECTION('',(-1.,0.,0.));
#884=AXIS2_PLACEMENT_3D('',#881,#882,#883);
#885=PLANE('',#884);
#886=ORIENTED_EDGE('',*,*,#184,.T.);
#887=ORIENTED_EDGE('',*,*,#876,.F.);
#888=DIRECTION('',(0.,0.,1.));
#889=VECTOR('',#888,1.);
#890=CARTESIAN_POINT('',(30.,25.1,25.1));
#891=LINE('',#890,#889);
#892=EDGE_CURVE('E349',#802,#869,#891,.T.);
#893=ORIENTED_EDGE('',*,*,#892,.F.);
#894=ORIENTED_EDGE('',*,*,#803,.T.);
#895=EDGE_LOOP('',(#886,#887,#893,#894));
#896=FACE_BOUND('',#895,.T.);
#897=ADVANCED_FACE('F1212',(#896),#885,.F.);
#898=CARTESIAN_POINT('',(30.,0.,0.));
#899=DIRECTION('',(1.,0.,0.));
#900=DIRECTION('',(0.,1.,0.));
#901=AXIS2_PLACEMENT_3D('',#898,#899,#900);
#902=PLANE('',#901);
#903=ORIENTED_EDGE('',*,*,#811,.T.);
#904=ORIENTED_EDGE('',*,*,#892,.T.);
#905=ORIENTED_EDGE('',*,*,#870,.T.);
#906=ORIENTED_EDGE('',*,*,#846,.T.);
#907=EDGE_LOOP('',(#903,#904,#905,#906));
#908=FACE_BOUND('',#907,.T.);
#909=ADVANCED_FACE('F1215',(#908),#902,.T.);
#910=CARTESIAN_POINT('',(25.1,30.,4.9));
#911=DIRECTION('',(1.,0.,0.));
#912=DIRECTION('',(0.,0.,-1.));
#913=AXIS2_PLACEMENT_3D('',#910,#911,#912);
#914=PLANE('',#913);
#915=ORIENTED_EDGE('',*,*,#329,.T.);
#916=DIRECTION('',(0.,1.,0.));
#917=VECTOR('',#916,1.);
#918=CARTESIAN_POINT('',(25.1,30.,4.9));
#919=LINE('',#918,#917);
#920=CARTESIAN_POINT('',(25.1,30.,4.9));
#921=VERTEX_POINT('',#920);
#922=EDGE_CURVE('E286',#921,#328,#919,.T.);
#923=ORIENTED_EDGE('',*,*,#922,.F.);
#924=DIRECTION('',(0.,0.,-1.));
#925=VECTOR('',#924,1.);
#926=CARTESIAN_POINT('',(25.1,30.,4.9));
#927=LINE('',#926,#925);
#928=CARTESIAN_POINT('',(25.1,30.,25.1));
#929=VERTEX_POINT('',#928);
#930=EDGE_CURVE('E290',#929,#921,#927,.T.);
#931=ORIENTED_EDGE('',*,*,#930,.F.);
#932=DIRECTION('',(0.,1.,0.));
#933=VECTOR('',#932,1.);
#934=CARTESIAN_POINT('',(25.1,30.,25.1));
#935=LINE('',#934,#933);
#936=EDGE_CURVE('E336',#929,#326,#935,.T.);
#937=ORIENTED_EDGE('',*,*,#936,.T.);
#938=EDGE_LOOP('',(#915,#923,#931,#937));
#939=FACE_BOUND('',#938,.T.);
#940=ADVANCED_FACE('F288',(#939),#914,.F.);
#941=CARTESIAN_POINT('',(4.9,30.,25.1));
#942=DIRECTION('',(0.,0.,1.));
#943=DIRECTION('',(1.,0.,0.));
#944=AXIS2_PLACEMENT_3D('',#941,#942,#943);
#945=PLANE('',#944);
#946=ORIENTED_EDGE('',*,*,#337,.T.);
#947=ORIENTED_EDGE('',*,*,#936,.F.);
#948=DIRECTION('',(1.,0.,0.));
#949=VECTOR('',#948,1.);
#950=CARTESIAN_POINT('',(4.9,30.,25.1));
#951=LINE('',#950,#949);
#952=CARTESIAN_POINT('',(4.9,30.,25.1));
#953=VERTEX_POINT('',#952);
#954=EDGE_CURVE('E299',#953,#929,#951,.T.);
#955=ORIENTED_EDGE('',*,*,#954,.F.);
#956=DIRECTION('',(0.,1.,0.));
#957=VECTOR('',#956,1.);
#958=CARTESIAN_POINT('',(4.9,30.,25.1));
#959=LINE('',#958,#957);
#960=EDGE_CURVE('E340',#953,#336,#959,.T.);
#961=ORIENTED_EDGE('',*,*,#960,.T.);
#962=EDGE_LOOP('',(#946,#947,#955,#961));
#963=FACE_BOUND('',#962,.T.);
#964=ADVANCED_FACE('F1267',(#963),#945,.F.);
#965=CARTESIAN_POINT('',(4.9,30.,4.9));
#966=DIRECTION('',(-1.,0.,0.));
#967=DIRECTION('',(0.,0.,1.));
#968=AXIS2_PLACEMENT_3D('',#965,#966,#967);
#969=PLANE('',#968);
#970=CARTESIAN_POINT('',(4.9,35.,15.));
#971=DIRECTION('',(-1.,0.,0.));
#972=DIRECTION('',(0.,0.,1.));
#973=AXIS2_PLACEMENT_3D('',#970,#971,#972);
#974=CIRCLE('',#973,2.);
#975=CARTESIAN_POINT('',(4.9,35.,17.));
#976=VERTEX_POINT('',#975);
#977=EDGE_CURVE('E51',#976,#976,#974,.T.);
#978=ORIENTED_EDGE('',*,*,#977,.T.);
#979=EDGE_LOOP('',(#978));
#980=FACE_BOUND('',#979,.T.);
#981=ORIENTED_EDGE('',*,*,#345,.T.);
#982=ORIENTED_EDGE('',*,*,#960,.F.);
#983=DIRECTION('',(0.,0.,1.));
#984=VECTOR('',#983,1.);
#985=CARTESIAN_POINT('',(4.9,30.,4.9));
#986=LINE('',#985,#984);
#987=CARTESIAN_POINT('',(4.9,30.,4.9));
#988=VERTEX_POINT('',#987);
#989=EDGE_CURVE('E308',#988,#953,#986,.T.);
#990=ORIENTED_EDGE('',*,*,#989,.F.);
#991=DIRECTION('',(0.,1.,0.));
#992=VECTOR('',#991,1.);
#993=CARTESIAN_POINT('',(4.9,30.,4.9));
#994=LINE('',#993,#992);
#995=EDGE_CURVE('E298',#988,#344,#994,.T.);
#996=ORIENTED_EDGE('',*,*,#995,.T.);
#997=EDGE_LOOP('',(#981,#982,#990,#996));
#998=FACE_BOUND('',#997,.T.);
#999=ADVANCED_FACE('F1207',(#980,#998),#969,.F.);
#1000=CARTESIAN_POINT('',(4.9,30.,4.9));
#1001=DIRECTION('',(0.,0.,-1.));
#1002=DIRECTION('',(-1.,0.,0.));
#1003=AXIS2_PLACEMENT_3D('',#1000,#1001,#1002);
#1004=PLANE('',#1003);
#1005=ORIENTED_EDGE('',*,*,#351,.T.);
#1006=ORIENTED_EDGE('',*,*,#995,.F.);
#1007=DIRECTION('',(-1.,0.,0.));
#1008=VECTOR('',#1007,1.);
#1009=CARTESIAN_POINT('',(4.9,30.,4.9));
#1010=LINE('',#1009,#1008);
#1011=EDGE_CURVE('E302',#921,#988,#1010,.T.);
#1012=ORIENTED_EDGE('',*,*,#1011,.F.);
#1013=ORIENTED_EDGE('',*,*,#922,.T.);
#1014=EDGE_LOOP('',(#1005,#1006,#1012,#1013));
#1015=FACE_BOUND('',#1014,.T.);
#1016=ADVANCED_FACE('F303',(#1015),#1004,.F.);
#1017=CARTESIAN_POINT('',(0.,30.,0.));
#1018=DIRECTION('',(0.,1.,0.));
#1019=DIRECTION('',(0.,0.,1.));
#1020=AXIS2_PLACEMENT_3D('',#1017,#1018,#1019);
#1021=PLANE('',#1020);
#1022=ORIENTED_EDGE('',*,*,#930,.T.);
#1023=ORIENTED_EDGE('',*,*,#1011,.T.);
#1024=ORIENTED_EDGE('',*,*,#989,.T.);
#1025=ORIENTED_EDGE('',*,*,#954,.T.);
#1026=EDGE_LOOP('',(#1022,#1023,#1024,#1025));
#1027=FACE_BOUND('',#1026,.T.);
#1028=ADVANCED_FACE('F310',(#1027),#1021,.T.);
#1029=CARTESIAN_POINT('',(28.,28.,40.));
#1030=DIRECTION('',(0.,0.,-1.));
#1031=DIRECTION('',(-1.,0.,0.));
#1032=AXIS2_PLACEMENT_3D('',#1029,#1030,#1031);
#1033=CYLINDRICAL_SURFACE('',#1032,2.);
#1034=ORIENTED_EDGE('',*,*,#593,.F.);
#1035=CARTESIAN_POINT('',(28.,28.,38.));
#1036=DIRECTION('',(0.,0.,-1.));
#1037=DIRECTION('',(-1.,0.,0.));
#1038=AXIS2_PLACEMENT_3D('',#1035,#1036,#1037);
#1039=CIRCLE('',#1038,2.);
#1040=EDGE_CURVE('E530',#586,#546,#1039,.T.);
#1041=ORIENTED_EDGE('',*,*,#1040,.T.);
#1042=ORIENTED_EDGE('',*,*,#547,.F.);
#1043=CARTESIAN_POINT('',(28.,28.,28.));
#1044=DIRECTION('',(0.707106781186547,0.,-0.707106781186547));
#1045=DIRECTION('',(0.707106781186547,0.,0.707106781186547));
#1046=AXIS2_PLACEMENT_3D('',#1043,#1044,#1045);
#1047=ELLIPSE('',#1046,2.82842712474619,2.);
#1048=CARTESIAN_POINT('',(29.4142135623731,29.4142135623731,29.4142135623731));
#1049=VERTEX_POINT('',#1048);
#1050=EDGE_CURVE('E471',#47,#1049,#1047,.F.);
#1051=ORIENTED_EDGE('',*,*,#1050,.T.);
#1052=CARTESIAN_POINT('',(28.,28.,28.));
#1053=DIRECTION('',(0.,-0.707106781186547,0.707106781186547));
#1054=DIRECTION('',(0.,-0.707106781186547,-0.707106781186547));
#1055=AXIS2_PLACEMENT_3D('',#1052,#1053,#1054);
#1056=ELLIPSE('',#1055,2.82842712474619,2.);
#1057=EDGE_CURVE('E467',#1049,#428,#1056,.T.);
#1058=ORIENTED_EDGE('',*,*,#1057,.T.);
#1059=EDGE_LOOP('',(#1034,#1041,#1042,#1051,#1058));
#1060=FACE_BOUND('',#1059,.T.);
#1061=ADVANCED_FACE('F789',(#1060),#1033,.T.);
#1062=CARTESIAN_POINT('',(0.,28.,28.));
#1063=DIRECTION('',(1.,0.,0.));
#1064=DIRECTION('',(0.,1.,0.));
#1065=AXIS2_PLACEMENT_3D('',#1062,#1063,#1064);
#1066=CYLINDRICAL_SURFACE('',#1065,2.);
#1067=ORIENTED_EDGE('',*,*,#48,.F.);
#1068=CARTESIAN_POINT('',(38.,28.,28.));
#1069=DIRECTION('',(1.,0.,0.));
#1070=DIRECTION('',(0.,1.,0.));
#1071=AXIS2_PLACEMENT_3D('',#1068,#1069,#1070);
#1072=CIRCLE('',#1071,2.);
#1073=EDGE_CURVE('E724',#39,#223,#1072,.F.);
#1074=ORIENTED_EDGE('',*,*,#1073,.T.);
#1075=ORIENTED_EDGE('',*,*,#224,.F.);
#1076=CARTESIAN_POINT('',(28.,28.,28.));
#1077=DIRECTION('',(0.707106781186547,-0.707106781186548,0.));
#1078=DIRECTION('',(-0.707106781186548,-0.707106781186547,0.));
#1079=AXIS2_PLACEMENT_3D('',#1076,#1077,#1078);
#1080=ELLIPSE('',#1079,2.82842712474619,2.);
#1081=EDGE_CURVE('E464',#221,#1049,#1080,.T.);
#1082=ORIENTED_EDGE('',*,*,#1081,.T.);
#1083=ORIENTED_EDGE('',*,*,#1050,.F.);
#1084=EDGE_LOOP('',(#1067,#1074,#1075,#1082,#1083));
#1085=FACE_BOUND('',#1084,.T.);
#1086=ADVANCED_FACE('F771',(#1085),#1066,.T.);
#1087=CARTESIAN_POINT('',(28.,40.,28.));
#1088=DIRECTION('',(0.,-1.,0.));
#1089=DIRECTION('',(0.,0.,-1.));
#1090=AXIS2_PLACEMENT_3D('',#1087,#1088,#1089);
#1091=CYLINDRICAL_SURFACE('',#1090,2.);
#1092=ORIENTED_EDGE('',*,*,#276,.F.);
#1093=CARTESIAN_POINT('',(28.,38.,28.));
#1094=DIRECTION('',(0.,-1.,0.));
#1095=DIRECTION('',(0.,0.,-1.));
#1096=AXIS2_PLACEMENT_3D('',#1093,#1094,#1095);
#1097=CIRCLE('',#1096,2.);
#1098=EDGE_CURVE('E628',#269,#430,#1097,.T.);
#1099=ORIENTED_EDGE('',*,*,#1098,.T.);
#1100=ORIENTED_EDGE('',*,*,#431,.F.);
#1101=ORIENTED_EDGE('',*,*,#1057,.F.);
#1102=ORIENTED_EDGE('',*,*,#1081,.F.);
#1103=EDGE_LOOP('',(#1092,#1099,#1100,#1101,#1102));
#1104=FACE_BOUND('',#1103,.T.);
#1105=ADVANCED_FACE('F784',(#1104),#1091,.T.);
#1106=CARTESIAN_POINT('',(28.,0.,2.));
#1107=DIRECTION('',(0.,1.,0.));
#1108=DIRECTION('',(0.,0.,1.));
#1109=AXIS2_PLACEMENT_3D('',#1106,#1107,#1108);
#1110=CYLINDRICAL_SURFACE('',#1109,2.);
#1111=ORIENTED_EDGE('',*,*,#531,.F.);
#1112=CARTESIAN_POINT('',(28.,38.,2.));
#1113=DIRECTION('',(0.,1.,0.));
#1114=DIRECTION('',(0.,0.,1.));
#1115=AXIS2_PLACEMENT_3D('',#1112,#1113,#1114);
#1116=CIRCLE('',#1115,2.);
#1117=EDGE_CURVE('E631',#524,#261,#1116,.F.);
#1118=ORIENTED_EDGE('',*,*,#1117,.T.);
#1119=ORIENTED_EDGE('',*,*,#262,.F.);
#1120=CARTESIAN_POINT('',(28.,28.,2.));
#1121=DIRECTION('',(-0.707106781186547,0.707106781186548,0.));
#1122=DIRECTION('',(-0.707106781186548,-0.707106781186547,0.));
#1123=AXIS2_PLACEMENT_3D('',#1120,#1121,#1122);
#1124=ELLIPSE('',#1123,2.82842712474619,2.);
#1125=EDGE_CURVE('E330',#490,#239,#1124,.F.);
#1126=ORIENTED_EDGE('',*,*,#1125,.F.);
#1127=EDGE_LOOP('',(#1111,#1118,#1119,#1126));
#1128=FACE_BOUND('',#1127,.T.);
#1129=ADVANCED_FACE('F973',(#1128),#1110,.T.);
#1130=CARTESIAN_POINT('',(40.,28.,2.));
#1131=DIRECTION('',(-1.,0.,0.));
#1132=DIRECTION('',(0.,-1.,0.));
#1133=AXIS2_PLACEMENT_3D('',#1130,#1131,#1132);
#1134=CYLINDRICAL_SURFACE('',#1133,2.);
#1135=ORIENTED_EDGE('',*,*,#240,.F.);
#1136=CARTESIAN_POINT('',(38.,28.,2.));
#1137=DIRECTION('',(-1.,0.,0.));
#1138=DIRECTION('',(0.,-1.,0.));
#1139=AXIS2_PLACEMENT_3D('',#1136,#1137,#1138);
#1140=CIRCLE('',#1139,2.);
#1141=EDGE_CURVE('E57',#231,#492,#1140,.T.);
#1142=ORIENTED_EDGE('',*,*,#1141,.T.);
#1143=ORIENTED_EDGE('',*,*,#493,.F.);
#1144=ORIENTED_EDGE('',*,*,#1125,.T.);
#1145=EDGE_LOOP('',(#1135,#1142,#1143,#1144));
#1146=FACE_BOUND('',#1145,.T.);
#1147=ADVANCED_FACE('F974',(#1146),#1134,.T.);
#1148=CARTESIAN_POINT('',(28.,2.,40.));
#1149=DIRECTION('',(0.,0.,1.));
#1150=DIRECTION('',(1.,0.,0.));
#1151=AXIS2_PLACEMENT_3D('',#1148,#1149,#1150);
#1152=CYLINDRICAL_SURFACE('',#1151,2.);
#1153=ORIENTED_EDGE('',*,*,#561,.F.);
#1154=CARTESIAN_POINT('',(28.,2.,38.));
#1155=DIRECTION('',(0.,0.,1.));
#1156=DIRECTION('',(1.,0.,0.));
#1157=AXIS2_PLACEMENT_3D('',#1154,#1155,#1156);
#1158=CIRCLE('',#1157,2.);
#1159=EDGE_CURVE('E524',#554,#117,#1158,.F.);
#1160=ORIENTED_EDGE('',*,*,#1159,.T.);
#1161=ORIENTED_EDGE('',*,*,#118,.F.);
#1162=CARTESIAN_POINT('',(28.,2.,28.));
#1163=DIRECTION('',(-0.707106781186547,0.,0.707106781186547));
#1164=DIRECTION('',(-0.707106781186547,0.,-0.707106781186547));
#1165=AXIS2_PLACEMENT_3D('',#1162,#1163,#1164);
#1166=ELLIPSE('',#1165,2.82842712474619,2.);
#1167=EDGE_CURVE('E492',#29,#109,#1166,.F.);
#1168=ORIENTED_EDGE('',*,*,#1167,.F.);
#1169=EDGE_LOOP('',(#1153,#1160,#1161,#1168));
#1170=FACE_BOUND('',#1169,.T.);
#1171=ADVANCED_FACE('F811',(#1170),#1152,.T.);
#1172=CARTESIAN_POINT('',(40.,2.,28.));
#1173=DIRECTION('',(-1.,0.,0.));
#1174=DIRECTION('',(0.,0.,1.));
#1175=AXIS2_PLACEMENT_3D('',#1172,#1173,#1174);
#1176=CYLINDRICAL_SURFACE('',#1175,2.);
#1177=ORIENTED_EDGE('',*,*,#110,.F.);
#1178=CARTESIAN_POINT('',(38.,2.,28.));
#1179=DIRECTION('',(-1.,0.,0.));
#1180=DIRECTION('',(0.,0.,1.));
#1181=AXIS2_PLACEMENT_3D('',#1178,#1179,#1180);
#1182=CIRCLE('',#1181,2.);
#1183=EDGE_CURVE('E718',#101,#31,#1182,.T.);
#1184=ORIENTED_EDGE('',*,*,#1183,.T.);
#1185=ORIENTED_EDGE('',*,*,#32,.F.);
#1186=ORIENTED_EDGE('',*,*,#1167,.T.);
#1187=EDGE_LOOP('',(#1177,#1184,#1185,#1186));
#1188=FACE_BOUND('',#1187,.T.);
#1189=ADVANCED_FACE('F980',(#1188),#1176,.T.);
#1190=CARTESIAN_POINT('',(0.,28.,38.));
#1191=DIRECTION('',(-1.,0.,0.));
#1192=DIRECTION('',(0.,-1.,0.));
#1193=AXIS2_PLACEMENT_3D('',#1190,#1191,#1192);
#1194=CYLINDRICAL_SURFACE('',#1193,2.);
#1195=ORIENTED_EDGE('',*,*,#587,.F.);
#1196=CARTESIAN_POINT('',(2.,28.,38.));
#1197=DIRECTION('',(-1.,0.,0.));
#1198=DIRECTION('',(0.,-1.,0.));
#1199=AXIS2_PLACEMENT_3D('',#1196,#1197,#1198);
#1200=CIRCLE('',#1199,2.);
#1201=EDGE_CURVE('E564',#578,#610,#1200,.F.);
#1202=ORIENTED_EDGE('',*,*,#1201,.T.);
#1203=ORIENTED_EDGE('',*,*,#611,.F.);
#1204=CARTESIAN_POINT('',(28.,28.,38.));
#1205=DIRECTION('',(1.,0.,0.));
#1206=DIRECTION('',(0.,0.,-1.));
#1207=AXIS2_PLACEMENT_3D('',#1204,#1205,#1206);
#1208=CIRCLE('',#1207,2.);
#1209=EDGE_CURVE('E510',#586,#608,#1208,.T.);
#1210=ORIENTED_EDGE('',*,*,#1209,.F.);
#1211=EDGE_LOOP('',(#1195,#1202,#1203,#1210));
#1212=FACE_BOUND('',#1211,.T.);
#1213=ADVANCED_FACE('F900',(#1212),#1194,.T.);
#1214=CARTESIAN_POINT('',(28.,28.,38.));
#1215=DIRECTION('',(0.,0.,-1.));
#1216=DIRECTION('',(-1.,0.,0.));
#1217=AXIS2_PLACEMENT_3D('',#1214,#1215,#1216);
#1218=SPHERICAL_SURFACE('',#1217,2.);
#1219=ORIENTED_EDGE('',*,*,#1040,.F.);
#1220=ORIENTED_EDGE('',*,*,#1209,.T.);
#1221=CARTESIAN_POINT('',(28.,28.,38.));
#1222=DIRECTION('',(0.,-1.,0.));
#1223=DIRECTION('',(0.,0.,-1.));
#1224=AXIS2_PLACEMENT_3D('',#1221,#1222,#1223);
#1225=CIRCLE('',#1224,2.);
#1226=EDGE_CURVE('E546',#546,#608,#1225,.T.);
#1227=ORIENTED_EDGE('',*,*,#1226,.F.);
#1228=EDGE_LOOP('',(#1219,#1220,#1227));
#1229=FACE_BOUND('',#1228,.T.);
#1230=ADVANCED_FACE('F799',(#1229),#1218,.T.);
#1231=CARTESIAN_POINT('',(28.,0.,38.));
#1232=DIRECTION('',(0.,1.,0.));
#1233=DIRECTION('',(-1.,0.,0.));
#1234=AXIS2_PLACEMENT_3D('',#1231,#1232,#1233);
#1235=CYLINDRICAL_SURFACE('',#1234,2.);
#1236=CARTESIAN_POINT('',(28.,2.,38.));
#1237=DIRECTION('',(0.,-1.,0.));
#1238=DIRECTION('',(1.,0.,0.));
#1239=AXIS2_PLACEMENT_3D('',#1236,#1237,#1238);
#1240=CIRCLE('',#1239,2.);
#1241=EDGE_CURVE('E541',#554,#626,#1240,.T.);
#1242=ORIENTED_EDGE('',*,*,#1241,.F.);
#1243=ORIENTED_EDGE('',*,*,#555,.F.);
#1244=ORIENTED_EDGE('',*,*,#1226,.T.);
#1245=ORIENTED_EDGE('',*,*,#633,.F.);
#1246=EDGE_LOOP('',(#1242,#1243,#1244,#1245));
#1247=FACE_BOUND('',#1246,.T.);
#1248=ADVANCED_FACE('F804',(#1247),#1235,.T.);
#1249=CARTESIAN_POINT('',(28.,2.,38.));
#1250=DIRECTION('',(0.,0.,-1.));
#1251=DIRECTION('',(-1.,0.,0.));
#1252=AXIS2_PLACEMENT_3D('',#1249,#1250,#1251);
#1253=SPHERICAL_SURFACE('',#1252,2.);
#1254=ORIENTED_EDGE('',*,*,#1159,.F.);
#1255=ORIENTED_EDGE('',*,*,#1241,.T.);
#1256=CARTESIAN_POINT('',(28.,2.,38.));
#1257=DIRECTION('',(-1.,0.,0.));
#1258=DIRECTION('',(0.,0.,1.));
#1259=AXIS2_PLACEMENT_3D('',#1256,#1257,#1258);
#1260=CIRCLE('',#1259,2.);
#1261=EDGE_CURVE('E537',#117,#626,#1260,.T.);
#1262=ORIENTED_EDGE('',*,*,#1261,.F.);
#1263=EDGE_LOOP('',(#1254,#1255,#1262));
#1264=FACE_BOUND('',#1263,.T.);
#1265=ADVANCED_FACE('F808',(#1264),#1253,.T.);
#1266=CARTESIAN_POINT('',(0.,2.,38.));
#1267=DIRECTION('',(-1.,0.,0.));
#1268=DIRECTION('',(0.,0.,1.));
#1269=AXIS2_PLACEMENT_3D('',#1266,#1267,#1268);
#1270=CYLINDRICAL_SURFACE('',#1269,2.);
#1271=ORIENTED_EDGE('',*,*,#627,.F.);
#1272=CARTESIAN_POINT('',(2.,2.,38.));
#1273=DIRECTION('',(-1.,0.,0.));
#1274=DIRECTION('',(0.,0.,1.));
#1275=AXIS2_PLACEMENT_3D('',#1272,#1273,#1274);
#1276=CIRCLE('',#1275,2.);
#1277=EDGE_CURVE('E571',#618,#125,#1276,.F.);
#1278=ORIENTED_EDGE('',*,*,#1277,.T.);
#1279=ORIENTED_EDGE('',*,*,#126,.F.);
#1280=ORIENTED_EDGE('',*,*,#1261,.T.);
#1281=EDGE_LOOP('',(#1271,#1278,#1279,#1280));
#1282=FACE_BOUND('',#1281,.T.);
#1283=ADVANCED_FACE('F820',(#1282),#1270,.T.);
#1284=CARTESIAN_POINT('',(2.,2.,30.));
#1285=DIRECTION('',(0.,0.,1.));
#1286=DIRECTION('',(1.,0.,0.));
#1287=AXIS2_PLACEMENT_3D('',#1284,#1285,#1286);
#1288=CYLINDRICAL_SURFACE('',#1287,2.);
#1289=ORIENTED_EDGE('',*,*,#396,.F.);
#1290=CARTESIAN_POINT('',(2.,2.,2.));
#1291=DIRECTION('',(0.,0.,1.));
#1292=DIRECTION('',(1.,0.,0.));
#1293=AXIS2_PLACEMENT_3D('',#1290,#1291,#1292);
#1294=CIRCLE('',#1293,2.);
#1295=EDGE_CURVE('E606',#387,#91,#1294,.T.);
#1296=ORIENTED_EDGE('',*,*,#1295,.T.);
#1297=ORIENTED_EDGE('',*,*,#132,.F.);
#1298=CARTESIAN_POINT('',(2.,2.,38.));
#1299=DIRECTION('',(0.,0.,1.));
#1300=DIRECTION('',(1.,0.,0.));
#1301=AXIS2_PLACEMENT_3D('',#1298,#1299,#1300);
#1302=CIRCLE('',#1301,2.);
#1303=EDGE_CURVE('E542',#395,#125,#1302,.T.);
#1304=ORIENTED_EDGE('',*,*,#1303,.F.);
#1305=EDGE_LOOP('',(#1289,#1296,#1297,#1304));
#1306=FACE_BOUND('',#1305,.T.);
#1307=ADVANCED_FACE('F839',(#1306),#1288,.T.);
#1308=CARTESIAN_POINT('',(2.,2.,38.));
#1309=DIRECTION('',(1.,0.,0.));
#1310=DIRECTION('',(0.,1.,0.));
#1311=AXIS2_PLACEMENT_3D('',#1308,#1309,#1310);
#1312=SPHERICAL_SURFACE('',#1311,2.);
#1313=ORIENTED_EDGE('',*,*,#1303,.T.);
#1314=ORIENTED_EDGE('',*,*,#1277,.F.);
#1315=CARTESIAN_POINT('',(2.,2.,38.));
#1316=DIRECTION('',(0.,1.,0.));
#1317=DIRECTION('',(0.,0.,1.));
#1318=AXIS2_PLACEMENT_3D('',#1315,#1316,#1317);
#1319=CIRCLE('',#1318,2.);
#1320=EDGE_CURVE('E587',#395,#618,#1319,.T.);
#1321=ORIENTED_EDGE('',*,*,#1320,.F.);
#1322=EDGE_LOOP('',(#1313,#1314,#1321));
#1323=FACE_BOUND('',#1322,.T.);
#1324=ADVANCED_FACE('F824',(#1323),#1312,.T.);
#1325=CARTESIAN_POINT('',(2.,0.,38.));
#1326=DIRECTION('',(0.,-1.,0.));
#1327=DIRECTION('',(1.,0.,0.));
#1328=AXIS2_PLACEMENT_3D('',#1325,#1326,#1327);
#1329=CYLINDRICAL_SURFACE('',#1328,2.);
#1330=ORIENTED_EDGE('',*,*,#1320,.T.);
#1331=ORIENTED_EDGE('',*,*,#619,.F.);
#1332=CARTESIAN_POINT('',(2.,28.,38.));
#1333=DIRECTION('',(0.,1.,0.));
#1334=DIRECTION('',(0.,0.,1.));
#1335=AXIS2_PLACEMENT_3D('',#1332,#1333,#1334);
#1336=CIRCLE('',#1335,2.);
#1337=EDGE_CURVE('E582',#403,#610,#1336,.T.);
#1338=ORIENTED_EDGE('',*,*,#1337,.F.);
#1339=ORIENTED_EDGE('',*,*,#404,.F.);
#1340=EDGE_LOOP('',(#1330,#1331,#1338,#1339));
#1341=FACE_BOUND('',#1340,.T.);
#1342=ADVANCED_FACE('F829',(#1341),#1329,.T.);
#1343=CARTESIAN_POINT('',(2.,28.,38.));
#1344=DIRECTION('',(1.,0.,0.));
#1345=DIRECTION('',(0.,1.,0.));
#1346=AXIS2_PLACEMENT_3D('',#1343,#1344,#1345);
#1347=SPHERICAL_SURFACE('',#1346,2.);
#1348=ORIENTED_EDGE('',*,*,#1337,.T.);
#1349=ORIENTED_EDGE('',*,*,#1201,.F.);
#1350=CARTESIAN_POINT('',(2.,28.,38.));
#1351=DIRECTION('',(0.,0.,-1.));
#1352=DIRECTION('',(-1.,0.,0.));
#1353=AXIS2_PLACEMENT_3D('',#1350,#1351,#1352);
#1354=CIRCLE('',#1353,2.);
#1355=EDGE_CURVE('E578',#403,#578,#1354,.T.);
#1356=ORIENTED_EDGE('',*,*,#1355,.F.);
#1357=EDGE_LOOP('',(#1348,#1349,#1356));
#1358=FACE_BOUND('',#1357,.T.);
#1359=ADVANCED_FACE('F897',(#1358),#1347,.T.);
#1360=CARTESIAN_POINT('',(2.,28.,30.));
#1361=DIRECTION('',(0.,0.,-1.));
#1362=DIRECTION('',(-1.,0.,0.));
#1363=AXIS2_PLACEMENT_3D('',#1360,#1361,#1362);
#1364=CYLINDRICAL_SURFACE('',#1363,2.);
#1365=ORIENTED_EDGE('',*,*,#1355,.T.);
#1366=ORIENTED_EDGE('',*,*,#579,.F.);
#1367=CARTESIAN_POINT('',(2.,28.,28.));
#1368=DIRECTION('',(0.,0.707106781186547,-0.707106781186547));
#1369=DIRECTION('',(0.,0.707106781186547,0.707106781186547));
#1370=AXIS2_PLACEMENT_3D('',#1367,#1368,#1369);
#1371=ELLIPSE('',#1370,2.82842712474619,2.);
#1372=EDGE_CURVE('E646',#446,#411,#1371,.F.);
#1373=ORIENTED_EDGE('',*,*,#1372,.T.);
#1374=ORIENTED_EDGE('',*,*,#412,.F.);
#1375=EDGE_LOOP('',(#1365,#1366,#1373,#1374));
#1376=FACE_BOUND('',#1375,.T.);
#1377=ADVANCED_FACE('F894',(#1376),#1364,.T.);
#1378=CARTESIAN_POINT('',(28.,38.,28.));
#1379=DIRECTION('',(0.,1.,0.));
#1380=DIRECTION('',(0.,0.,1.));
#1381=AXIS2_PLACEMENT_3D('',#1378,#1379,#1380);
#1382=SPHERICAL_SURFACE('',#1381,2.);
#1383=CARTESIAN_POINT('',(28.,38.,28.));
#1384=DIRECTION('',(-1.,0.,0.));
#1385=DIRECTION('',(0.,0.,1.));
#1386=AXIS2_PLACEMENT_3D('',#1383,#1384,#1385);
#1387=CIRCLE('',#1386,2.);
#1388=EDGE_CURVE('E692',#430,#310,#1387,.T.);
#1389=ORIENTED_EDGE('',*,*,#1388,.F.);
#1390=ORIENTED_EDGE('',*,*,#1098,.F.);
#1391=CARTESIAN_POINT('',(28.,38.,28.));
#1392=DIRECTION('',(0.,0.,-1.));
#1393=DIRECTION('',(-1.,0.,0.));
#1394=AXIS2_PLACEMENT_3D('',#1391,#1392,#1393);
#1395=CIRCLE('',#1394,2.);
#1396=EDGE_CURVE('E583',#310,#269,#1395,.T.);
#1397=ORIENTED_EDGE('',*,*,#1396,.F.);
#1398=EDGE_LOOP('',(#1389,#1390,#1397));
#1399=FACE_BOUND('',#1398,.T.);
#1400=ADVANCED_FACE('F998',(#1399),#1382,.T.);
#1401=CARTESIAN_POINT('',(28.,38.,30.));
#1402=DIRECTION('',(0.,0.,-1.));
#1403=DIRECTION('',(-1.,0.,0.));
#1404=AXIS2_PLACEMENT_3D('',#1401,#1402,#1403);
#1405=CYLINDRICAL_SURFACE('',#1404,2.);
#1406=ORIENTED_EDGE('',*,*,#1396,.T.);
#1407=ORIENTED_EDGE('',*,*,#270,.F.);
#1408=CARTESIAN_POINT('',(28.,38.,2.));
#1409=DIRECTION('',(0.,0.,-1.));
#1410=DIRECTION('',(-1.,0.,0.));
#1411=AXIS2_PLACEMENT_3D('',#1408,#1409,#1410);
#1412=CIRCLE('',#1411,2.);
#1413=EDGE_CURVE('E688',#292,#261,#1412,.T.);
#1414=ORIENTED_EDGE('',*,*,#1413,.F.);
#1415=ORIENTED_EDGE('',*,*,#317,.F.);
#1416=EDGE_LOOP('',(#1406,#1407,#1414,#1415));
#1417=FACE_BOUND('',#1416,.T.);
#1418=ADVANCED_FACE('F1028',(#1417),#1405,.T.);
#1419=CARTESIAN_POINT('',(0.,38.,28.));
#1420=DIRECTION('',(1.,0.,0.));
#1421=DIRECTION('',(0.,0.,-1.));
#1422=AXIS2_PLACEMENT_3D('',#1419,#1420,#1421);
#1423=CYLINDRICAL_SURFACE('',#1422,2.);
#1424=ORIENTED_EDGE('',*,*,#1388,.T.);
#1425=ORIENTED_EDGE('',*,*,#311,.F.);
#1426=CARTESIAN_POINT('',(2.,38.,28.));
#1427=DIRECTION('',(-1.,0.,0.));
#1428=DIRECTION('',(0.,0.,1.));
#1429=AXIS2_PLACEMENT_3D('',#1426,#1427,#1428);
#1430=CIRCLE('',#1429,2.);
#1431=EDGE_CURVE('E684',#438,#302,#1430,.T.);
#1432=ORIENTED_EDGE('',*,*,#1431,.F.);
#1433=ORIENTED_EDGE('',*,*,#439,.F.);
#1434=EDGE_LOOP('',(#1424,#1425,#1432,#1433));
#1435=FACE_BOUND('',#1434,.T.);
#1436=ADVANCED_FACE('F876',(#1435),#1423,.T.);
#1437=CARTESIAN_POINT('',(2.,0.,28.));
#1438=DIRECTION('',(0.,1.,0.));
#1439=DIRECTION('',(-1.,0.,0.));
#1440=AXIS2_PLACEMENT_3D('',#1437,#1438,#1439);
#1441=CYLINDRICAL_SURFACE('',#1440,2.);
#1442=ORIENTED_EDGE('',*,*,#1372,.F.);
#1443=ORIENTED_EDGE('',*,*,#447,.F.);
#1444=CARTESIAN_POINT('',(2.,38.,28.));
#1445=DIRECTION('',(0.,1.,0.));
#1446=DIRECTION('',(0.,0.,1.));
#1447=AXIS2_PLACEMENT_3D('',#1444,#1445,#1446);
#1448=CIRCLE('',#1447,2.);
#1449=EDGE_CURVE('E680',#377,#438,#1448,.T.);
#1450=ORIENTED_EDGE('',*,*,#1449,.F.);
#1451=ORIENTED_EDGE('',*,*,#418,.F.);
#1452=EDGE_LOOP('',(#1442,#1443,#1450,#1451));
#1453=FACE_BOUND('',#1452,.T.);
#1454=ADVANCED_FACE('F886',(#1453),#1441,.T.);
#1455=CARTESIAN_POINT('',(28.,38.,2.));
#1456=DIRECTION('',(0.,1.,0.));
#1457=DIRECTION('',(0.,0.,1.));
#1458=AXIS2_PLACEMENT_3D('',#1455,#1456,#1457);
#1459=SPHERICAL_SURFACE('',#1458,2.);
#1460=ORIENTED_EDGE('',*,*,#1413,.T.);
#1461=ORIENTED_EDGE('',*,*,#1117,.F.);
#1462=CARTESIAN_POINT('',(28.,38.,2.));
#1463=DIRECTION('',(-1.,0.,0.));
#1464=DIRECTION('',(0.,0.,1.));
#1465=AXIS2_PLACEMENT_3D('',#1462,#1463,#1464);
#1466=CIRCLE('',#1465,2.);
#1467=EDGE_CURVE('E676',#292,#524,#1466,.T.);
#1468=ORIENTED_EDGE('',*,*,#1467,.F.);
#1469=EDGE_LOOP('',(#1460,#1461,#1468));
#1470=FACE_BOUND('',#1469,.T.);
#1471=ADVANCED_FACE('F1020',(#1470),#1459,.T.);
#1472=CARTESIAN_POINT('',(2.,38.,28.));
#1473=DIRECTION('',(0.,0.,1.));
#1474=DIRECTION('',(1.,0.,0.));
#1475=AXIS2_PLACEMENT_3D('',#1472,#1473,#1474);
#1476=SPHERICAL_SURFACE('',#1475,2.);
#1477=ORIENTED_EDGE('',*,*,#1449,.T.);
#1478=ORIENTED_EDGE('',*,*,#1431,.T.);
#1479=CARTESIAN_POINT('',(2.,38.,28.));
#1480=DIRECTION('',(0.,0.,1.));
#1481=DIRECTION('',(1.,0.,0.));
#1482=AXIS2_PLACEMENT_3D('',#1479,#1480,#1481);
#1483=CIRCLE('',#1482,2.);
#1484=EDGE_CURVE('E672',#377,#302,#1483,.F.);
#1485=ORIENTED_EDGE('',*,*,#1484,.F.);
#1486=EDGE_LOOP('',(#1477,#1478,#1485));
#1487=FACE_BOUND('',#1486,.T.);
#1488=ADVANCED_FACE('F880',(#1487),#1476,.T.);
#1489=CARTESIAN_POINT('',(0.,38.,2.));
#1490=DIRECTION('',(-1.,0.,0.));
#1491=DIRECTION('',(0.,0.,1.));
#1492=AXIS2_PLACEMENT_3D('',#1489,#1490,#1491);
#1493=CYLINDRICAL_SURFACE('',#1492,2.);
#1494=ORIENTED_EDGE('',*,*,#1467,.T.);
#1495=ORIENTED_EDGE('',*,*,#525,.F.);
#1496=CARTESIAN_POINT('',(2.,38.,2.));
#1497=DIRECTION('',(-1.,0.,0.));
#1498=DIRECTION('',(0.,0.,1.));
#1499=AXIS2_PLACEMENT_3D('',#1496,#1497,#1498);
#1500=CIRCLE('',#1499,2.);
#1501=EDGE_CURVE('E668',#294,#516,#1500,.T.);
#1502=ORIENTED_EDGE('',*,*,#1501,.F.);
#1503=ORIENTED_EDGE('',*,*,#295,.F.);
#1504=EDGE_LOOP('',(#1494,#1495,#1502,#1503));
#1505=FACE_BOUND('',#1504,.T.);
#1506=ADVANCED_FACE('F859',(#1505),#1493,.T.);
#1507=CARTESIAN_POINT('',(2.,38.,30.));
#1508=DIRECTION('',(0.,0.,1.));
#1509=DIRECTION('',(1.,0.,0.));
#1510=AXIS2_PLACEMENT_3D('',#1507,#1508,#1509);
#1511=CYLINDRICAL_SURFACE('',#1510,2.);
#1512=ORIENTED_EDGE('',*,*,#1484,.T.);
#1513=ORIENTED_EDGE('',*,*,#303,.F.);
#1514=CARTESIAN_POINT('',(2.,38.,2.));
#1515=DIRECTION('',(0.,0.,-1.));
#1516=DIRECTION('',(0.,1.,0.));
#1517=AXIS2_PLACEMENT_3D('',#1514,#1515,#1516);
#1518=CIRCLE('',#1517,2.);
#1519=EDGE_CURVE('E664',#379,#294,#1518,.T.);
#1520=ORIENTED_EDGE('',*,*,#1519,.F.);
#1521=ORIENTED_EDGE('',*,*,#380,.F.);
#1522=EDGE_LOOP('',(#1512,#1513,#1520,#1521));
#1523=FACE_BOUND('',#1522,.T.);
#1524=ADVANCED_FACE('F868',(#1523),#1511,.T.);
#1525=CARTESIAN_POINT('',(2.,38.,2.));
#1526=DIRECTION('',(0.,1.,0.));
#1527=DIRECTION('',(0.,0.,1.));
#1528=AXIS2_PLACEMENT_3D('',#1525,#1526,#1527);
#1529=SPHERICAL_SURFACE('',#1528,2.);
#1530=ORIENTED_EDGE('',*,*,#1519,.T.);
#1531=ORIENTED_EDGE('',*,*,#1501,.T.);
#1532=CARTESIAN_POINT('',(2.,38.,2.));
#1533=DIRECTION('',(0.,1.,0.));
#1534=DIRECTION('',(0.,0.,1.));
#1535=AXIS2_PLACEMENT_3D('',#1532,#1533,#1534);
#1536=CIRCLE('',#1535,2.);
#1537=EDGE_CURVE('E660',#379,#516,#1536,.F.);
#1538=ORIENTED_EDGE('',*,*,#1537,.F.);
#1539=EDGE_LOOP('',(#1530,#1531,#1538));
#1540=FACE_BOUND('',#1539,.T.);
#1541=ADVANCED_FACE('F863',(#1540),#1529,.T.);
#1542=CARTESIAN_POINT('',(2.,40.,2.));
#1543=DIRECTION('',(0.,-1.,0.));
#1544=DIRECTION('',(1.,0.,0.));
#1545=AXIS2_PLACEMENT_3D('',#1542,#1543,#1544);
#1546=CYLINDRICAL_SURFACE('',#1545,2.);
#1547=CARTESIAN_POINT('',(2.,2.,2.));
#1548=DIRECTION('',(0.,-1.,0.));
#1549=DIRECTION('',(0.,0.,-1.));
#1550=AXIS2_PLACEMENT_3D('',#1547,#1548,#1549);
#1551=CIRCLE('',#1550,2.);
#1552=EDGE_CURVE('E655',#387,#508,#1551,.T.);
#1553=ORIENTED_EDGE('',*,*,#1552,.F.);
#1554=ORIENTED_EDGE('',*,*,#388,.F.);
#1555=ORIENTED_EDGE('',*,*,#1537,.T.);
#1556=ORIENTED_EDGE('',*,*,#517,.F.);
#1557=EDGE_LOOP('',(#1553,#1554,#1555,#1556));
#1558=FACE_BOUND('',#1557,.T.);
#1559=ADVANCED_FACE('F851',(#1558),#1546,.T.);
#1560=CARTESIAN_POINT('',(2.,2.,2.));
#1561=DIRECTION('',(0.,0.,1.));
#1562=DIRECTION('',(1.,0.,0.));
#1563=AXIS2_PLACEMENT_3D('',#1560,#1561,#1562);
#1564=SPHERICAL_SURFACE('',#1563,2.);
#1565=ORIENTED_EDGE('',*,*,#1295,.F.);
#1566=ORIENTED_EDGE('',*,*,#1552,.T.);
#1567=CARTESIAN_POINT('',(2.,2.,2.));
#1568=DIRECTION('',(1.,0.,0.));
#1569=DIRECTION('',(0.,0.,-1.));
#1570=AXIS2_PLACEMENT_3D('',#1567,#1568,#1569);
#1571=CIRCLE('',#1570,2.);
#1572=EDGE_CURVE('E651',#91,#508,#1571,.T.);
#1573=ORIENTED_EDGE('',*,*,#1572,.F.);
#1574=EDGE_LOOP('',(#1565,#1566,#1573));
#1575=FACE_BOUND('',#1574,.T.);
#1576=ADVANCED_FACE('F848',(#1575),#1564,.T.);
#1577=CARTESIAN_POINT('',(0.,2.,2.));
#1578=DIRECTION('',(1.,0.,0.));
#1579=DIRECTION('',(0.,0.,-1.));
#1580=AXIS2_PLACEMENT_3D('',#1577,#1578,#1579);
#1581=CYLINDRICAL_SURFACE('',#1580,2.);
#1582=ORIENTED_EDGE('',*,*,#509,.F.);
#1583=CARTESIAN_POINT('',(38.,2.,2.));
#1584=DIRECTION('',(1.,0.,0.));
#1585=DIRECTION('',(0.,0.,-1.));
#1586=AXIS2_PLACEMENT_3D('',#1583,#1584,#1585);
#1587=CIRCLE('',#1586,2.);
#1588=EDGE_CURVE('E650',#500,#93,#1587,.F.);
#1589=ORIENTED_EDGE('',*,*,#1588,.T.);
#1590=ORIENTED_EDGE('',*,*,#94,.F.);
#1591=ORIENTED_EDGE('',*,*,#1572,.T.);
#1592=EDGE_LOOP('',(#1582,#1589,#1590,#1591));
#1593=FACE_BOUND('',#1592,.T.);
#1594=ADVANCED_FACE('F845',(#1593),#1581,.T.);
#1595=CARTESIAN_POINT('',(38.,28.,28.));
#1596=DIRECTION('',(-1.,0.,0.));
#1597=DIRECTION('',(0.,-1.,0.));
#1598=AXIS2_PLACEMENT_3D('',#1595,#1596,#1597);
#1599=SPHERICAL_SURFACE('',#1598,2.);
#1600=CARTESIAN_POINT('',(38.,28.,28.));
#1601=DIRECTION('',(0.,0.,-1.));
#1602=DIRECTION('',(-1.,0.,0.));
#1603=AXIS2_PLACEMENT_3D('',#1600,#1601,#1602);
#1604=CIRCLE('',#1603,2.);
#1605=EDGE_CURVE('E754',#223,#147,#1604,.T.);
#1606=ORIENTED_EDGE('',*,*,#1605,.F.);
#1607=ORIENTED_EDGE('',*,*,#1073,.F.);
#1608=CARTESIAN_POINT('',(38.,28.,28.));
#1609=DIRECTION('',(0.,-1.,0.));
#1610=DIRECTION('',(0.,0.,-1.));
#1611=AXIS2_PLACEMENT_3D('',#1608,#1609,#1610);
#1612=CIRCLE('',#1611,2.);
#1613=EDGE_CURVE('E656',#147,#39,#1612,.T.);
#1614=ORIENTED_EDGE('',*,*,#1613,.F.);
#1615=EDGE_LOOP('',(#1606,#1607,#1614));
#1616=FACE_BOUND('',#1615,.T.);
#1617=ADVANCED_FACE('F49',(#1616),#1599,.T.);
#1618=CARTESIAN_POINT('',(38.,0.,28.));
#1619=DIRECTION('',(0.,-1.,0.));
#1620=DIRECTION('',(1.,0.,0.));
#1621=AXIS2_PLACEMENT_3D('',#1618,#1619,#1620);
#1622=CYLINDRICAL_SURFACE('',#1621,2.);
#1623=ORIENTED_EDGE('',*,*,#1613,.T.);
#1624=ORIENTED_EDGE('',*,*,#40,.F.);
#1625=CARTESIAN_POINT('',(38.,2.,28.));
#1626=DIRECTION('',(0.,-1.,0.));
#1627=DIRECTION('',(1.,0.,0.));
#1628=AXIS2_PLACEMENT_3D('',#1625,#1626,#1627);
#1629=CIRCLE('',#1628,2.);
#1630=EDGE_CURVE('E750',#149,#31,#1629,.T.);
#1631=ORIENTED_EDGE('',*,*,#1630,.F.);
#1632=ORIENTED_EDGE('',*,*,#150,.F.);
#1633=EDGE_LOOP('',(#1623,#1624,#1631,#1632));
#1634=FACE_BOUND('',#1633,.T.);
#1635=ADVANCED_FACE('F763',(#1634),#1622,.T.);
#1636=CARTESIAN_POINT('',(38.,28.,30.));
#1637=DIRECTION('',(0.,0.,-1.));
#1638=DIRECTION('',(-1.,0.,0.));
#1639=AXIS2_PLACEMENT_3D('',#1636,#1637,#1638);
#1640=CYLINDRICAL_SURFACE('',#1639,2.);
#1641=ORIENTED_EDGE('',*,*,#1605,.T.);
#1642=ORIENTED_EDGE('',*,*,#172,.F.);
#1643=CARTESIAN_POINT('',(38.,28.,2.));
#1644=DIRECTION('',(0.,0.,-1.));
#1645=DIRECTION('',(-1.,0.,0.));
#1646=AXIS2_PLACEMENT_3D('',#1643,#1644,#1645);
#1647=CIRCLE('',#1646,2.);
#1648=EDGE_CURVE('E746',#231,#165,#1647,.T.);
#1649=ORIENTED_EDGE('',*,*,#1648,.F.);
#1650=ORIENTED_EDGE('',*,*,#232,.F.);
#1651=EDGE_LOOP('',(#1641,#1642,#1649,#1650));
#1652=FACE_BOUND('',#1651,.T.);
#1653=ADVANCED_FACE('F1055',(#1652),#1640,.T.);
#1654=CARTESIAN_POINT('',(38.,2.,28.));
#1655=DIRECTION('',(-1.,0.,0.));
#1656=DIRECTION('',(0.,-1.,0.));
#1657=AXIS2_PLACEMENT_3D('',#1654,#1655,#1656);
#1658=SPHERICAL_SURFACE('',#1657,2.);
#1659=ORIENTED_EDGE('',*,*,#1630,.T.);
#1660=ORIENTED_EDGE('',*,*,#1183,.F.);
#1661=CARTESIAN_POINT('',(38.,2.,28.));
#1662=DIRECTION('',(0.,0.,-1.));
#1663=DIRECTION('',(-1.,0.,0.));
#1664=AXIS2_PLACEMENT_3D('',#1661,#1662,#1663);
#1665=CIRCLE('',#1664,2.);
#1666=EDGE_CURVE('E742',#149,#101,#1665,.T.);
#1667=ORIENTED_EDGE('',*,*,#1666,.F.);
#1668=EDGE_LOOP('',(#1659,#1660,#1667));
#1669=FACE_BOUND('',#1668,.T.);
#1670=ADVANCED_FACE('F1051',(#1669),#1658,.T.);
#1671=CARTESIAN_POINT('',(38.,28.,2.));
#1672=DIRECTION('',(-1.,0.,0.));
#1673=DIRECTION('',(0.,-1.,0.));
#1674=AXIS2_PLACEMENT_3D('',#1671,#1672,#1673);
#1675=SPHERICAL_SURFACE('',#1674,2.);
#1676=ORIENTED_EDGE('',*,*,#1141,.F.);
#1677=ORIENTED_EDGE('',*,*,#1648,.T.);
#1678=CARTESIAN_POINT('',(38.,28.,2.));
#1679=DIRECTION('',(0.,-1.,0.));
#1680=DIRECTION('',(0.,0.,-1.));
#1681=AXIS2_PLACEMENT_3D('',#1678,#1679,#1680);
#1682=CIRCLE('',#1681,2.);
#1683=EDGE_CURVE('E738',#492,#165,#1682,.T.);
#1684=ORIENTED_EDGE('',*,*,#1683,.F.);
#1685=EDGE_LOOP('',(#1676,#1677,#1684));
#1686=FACE_BOUND('',#1685,.T.);
#1687=ADVANCED_FACE('F1047',(#1686),#1675,.T.);
#1688=CARTESIAN_POINT('',(38.,2.,30.));
#1689=DIRECTION('',(0.,0.,1.));
#1690=DIRECTION('',(1.,0.,0.));
#1691=AXIS2_PLACEMENT_3D('',#1688,#1689,#1690);
#1692=CYLINDRICAL_SURFACE('',#1691,2.);
#1693=ORIENTED_EDGE('',*,*,#1666,.T.);
#1694=ORIENTED_EDGE('',*,*,#102,.F.);
#1695=CARTESIAN_POINT('',(38.,2.,2.));
#1696=DIRECTION('',(0.,0.,-1.));
#1697=DIRECTION('',(-1.,0.,0.));
#1698=AXIS2_PLACEMENT_3D('',#1695,#1696,#1697);
#1699=CIRCLE('',#1698,2.);
#1700=EDGE_CURVE('E734',#157,#93,#1699,.T.);
#1701=ORIENTED_EDGE('',*,*,#1700,.F.);
#1702=ORIENTED_EDGE('',*,*,#158,.F.);
#1703=EDGE_LOOP('',(#1693,#1694,#1701,#1702));
#1704=FACE_BOUND('',#1703,.T.);
#1705=ADVANCED_FACE('F1043',(#1704),#1692,.T.);
#1706=CARTESIAN_POINT('',(38.,0.,2.));
#1707=DIRECTION('',(0.,1.,0.));
#1708=DIRECTION('',(-1.,0.,0.));
#1709=AXIS2_PLACEMENT_3D('',#1706,#1707,#1708);
#1710=CYLINDRICAL_SURFACE('',#1709,2.);
#1711=ORIENTED_EDGE('',*,*,#1683,.T.);
#1712=ORIENTED_EDGE('',*,*,#166,.F.);
#1713=CARTESIAN_POINT('',(38.,2.,2.));
#1714=DIRECTION('',(0.,-1.,0.));
#1715=DIRECTION('',(1.,0.,0.));
#1716=AXIS2_PLACEMENT_3D('',#1713,#1714,#1715);
#1717=CIRCLE('',#1716,2.);
#1718=EDGE_CURVE('E731',#500,#157,#1717,.T.);
#1719=ORIENTED_EDGE('',*,*,#1718,.F.);
#1720=ORIENTED_EDGE('',*,*,#501,.F.);
#1721=EDGE_LOOP('',(#1711,#1712,#1719,#1720));
#1722=FACE_BOUND('',#1721,.T.);
#1723=ADVANCED_FACE('F1039',(#1722),#1710,.T.);
#1724=CARTESIAN_POINT('',(38.,2.,2.));
#1725=DIRECTION('',(-1.,0.,0.));
#1726=DIRECTION('',(0.,-1.,0.));
#1727=AXIS2_PLACEMENT_3D('',#1724,#1725,#1726);
#1728=SPHERICAL_SURFACE('',#1727,2.);
#1729=ORIENTED_EDGE('',*,*,#1700,.T.);
#1730=ORIENTED_EDGE('',*,*,#1588,.F.);
#1731=ORIENTED_EDGE('',*,*,#1718,.T.);
#1732=EDGE_LOOP('',(#1729,#1730,#1731));
#1733=FACE_BOUND('',#1732,.T.);
#1734=ADVANCED_FACE('F1035',(#1733),#1728,.T.);
#1735=CARTESIAN_POINT('',(15.13,8.,10.));
#1736=DIRECTION('',(0.,0.,-1.));
#1737=DIRECTION('',(-1.,0.,0.));
#1738=AXIS2_PLACEMENT_3D('',#1735,#1736,#1737);
#1739=CYLINDRICAL_SURFACE('',#1738,2.5);
#1740=CARTESIAN_POINT('',(15.13,8.,10.));
#1741=DIRECTION('',(0.,0.,-1.));
#1742=DIRECTION('',(-1.,0.,0.));
#1743=AXIS2_PLACEMENT_3D('',#1740,#1741,#1742);
#1744=CIRCLE('',#1743,2.5);
#1745=CARTESIAN_POINT('',(12.63,8.,10.));
#1746=VERTEX_POINT('',#1745);
#1747=EDGE_CURVE('E320',#1746,#1746,#1744,.T.);
#1748=ORIENTED_EDGE('',*,*,#1747,.F.);
#1749=EDGE_LOOP('',(#1748));
#1750=FACE_BOUND('',#1749,.T.);
#1751=ORIENTED_EDGE('',*,*,#481,.T.);
#1752=EDGE_LOOP('',(#1751));
#1753=FACE_BOUND('',#1752,.T.);
#1754=ADVANCED_FACE('F1038',(#1750,#1753),#1739,.F.);
#1755=CARTESIAN_POINT('',(15.13,8.,10.));
#1756=DIRECTION('',(0.,0.,-1.));
#1757=DIRECTION('',(-1.,0.,0.));
#1758=AXIS2_PLACEMENT_3D('',#1755,#1756,#1757);
#1759=PLANE('',#1758);
#1760=ORIENTED_EDGE('',*,*,#1747,.T.);
#1761=EDGE_LOOP('',(#1760));
#1762=FACE_BOUND('',#1761,.T.);
#1763=ADVANCED_FACE('F1477',(#1762),#1759,.T.);
#1764=CARTESIAN_POINT('',(15.13,23.,10.));
#1765=DIRECTION('',(0.,0.,-1.));
#1766=DIRECTION('',(-1.,0.,0.));
#1767=AXIS2_PLACEMENT_3D('',#1764,#1765,#1766);
#1768=CYLINDRICAL_SURFACE('',#1767,2.5);
#1769=CARTESIAN_POINT('',(15.13,23.,10.));
#1770=DIRECTION('',(0.,0.,-1.));
#1771=DIRECTION('',(-1.,0.,0.));
#1772=AXIS2_PLACEMENT_3D('',#1769,#1770,#1771);
#1773=CIRCLE('',#1772,2.5);
#1774=CARTESIAN_POINT('',(12.63,23.,10.));
#1775=VERTEX_POINT('',#1774);
#1776=EDGE_CURVE('E735',#1775,#1775,#1773,.T.);
#1777=ORIENTED_EDGE('',*,*,#1776,.F.);
#1778=EDGE_LOOP('',(#1777));
#1779=FACE_BOUND('',#1778,.T.);
#1780=ORIENTED_EDGE('',*,*,#470,.T.);
#1781=EDGE_LOOP('',(#1780));
#1782=FACE_BOUND('',#1781,.T.);
#1783=ADVANCED_FACE('F1486',(#1779,#1782),#1768,.F.);
#1784=CARTESIAN_POINT('',(15.13,23.,10.));
#1785=DIRECTION('',(0.,0.,-1.));
#1786=DIRECTION('',(-1.,0.,0.));
#1787=AXIS2_PLACEMENT_3D('',#1784,#1785,#1786);
#1788=PLANE('',#1787);
#1789=ORIENTED_EDGE('',*,*,#1776,.T.);
#1790=EDGE_LOOP('',(#1789));
#1791=FACE_BOUND('',#1790,.T.);
#1792=ADVANCED_FACE('F1157',(#1791),#1788,.T.);
#1793=CARTESIAN_POINT('',(35.,-9.00000000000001,15.));
#1794=DIRECTION('',(0.,1.,0.));
#1795=DIRECTION('',(-1.,0.,0.));
#1796=AXIS2_PLACEMENT_3D('',#1793,#1794,#1795);
#1797=CYLINDRICAL_SURFACE('',#1796,2.);
#1798=ORIENTED_EDGE('',*,*,#82,.T.);
#1799=EDGE_LOOP('',(#1798));
#1800=FACE_BOUND('',#1799,.T.);
#1801=ORIENTED_EDGE('',*,*,#834,.F.);
#1802=EDGE_LOOP('',(#1801));
#1803=FACE_BOUND('',#1802,.T.);
#1804=ADVANCED_FACE('F1181',(#1800,#1803),#1797,.F.);
#1805=CARTESIAN_POINT('',(15.,-9.00000000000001,35.));
#1806=DIRECTION('',(0.,1.,0.));
#1807=DIRECTION('',(-1.,0.,0.));
#1808=AXIS2_PLACEMENT_3D('',#1805,#1806,#1807);
#1809=CYLINDRICAL_SURFACE('',#1808,2.00000000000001);
#1810=ORIENTED_EDGE('',*,*,#71,.T.);
#1811=EDGE_LOOP('',(#1810));
#1812=FACE_BOUND('',#1811,.T.);
#1813=ORIENTED_EDGE('',*,*,#715,.F.);
#1814=EDGE_LOOP('',(#1813));
#1815=FACE_BOUND('',#1814,.T.);
#1816=ADVANCED_FACE('F1184',(#1812,#1815),#1809,.F.);
#1817=CARTESIAN_POINT('',(10.,35.,15.));
#1818=DIRECTION('',(-1.,0.,0.));
#1819=DIRECTION('',(0.,-1.,0.));
#1820=AXIS2_PLACEMENT_3D('',#1817,#1818,#1819);
#1821=CYLINDRICAL_SURFACE('',#1820,2.);
#1822=ORIENTED_EDGE('',*,*,#368,.T.);
#1823=EDGE_LOOP('',(#1822));
#1824=FACE_BOUND('',#1823,.T.);
#1825=ORIENTED_EDGE('',*,*,#977,.F.);
#1826=EDGE_LOOP('',(#1825));
#1827=FACE_BOUND('',#1826,.T.);
#1828=ADVANCED_FACE('F1192',(#1824,#1827),#1821,.F.);
#1829=CLOSED_SHELL('',(#58,#136,#210,#250,#281,#355,#422,#457,#535,#566,#597,#671,#702,#737,
#761,#778,#790,#821,#856,#880,#897,#909,#940,#964,#999,#1016,#1028,#1061,#1086,#1105,#1129,
#1147,#1171,#1189,#1213,#1230,#1248,#1265,#1283,#1307,#1324,#1342,#1359,#1377,#1400,#1418,#1436,
#1454,#1471,#1488,#1506,#1524,#1541,#1559,#1576,#1594,#1617,#1635,#1653,#1670,#1687,#1705,#1723,
#1734,#1754,#1763,#1783,#1792,#1804,#1816,#1828));
#1830=MANIFOLD_SOLID_BREP('B2',#1829);
#1831=ADVANCED_BREP_SHAPE_REPRESENTATION('',(#18,#1830),#14);
#1832=SHAPE_DEFINITION_REPRESENTATION(#9,#1831);
ENDSEC;
END-ISO-10303-21;
